VERSION 5.7 ;
  NOWIREEXTENSIONATPIN ON ;
  DIVIDERCHAR "/" ;
  BUSBITCHARS "[]" ;
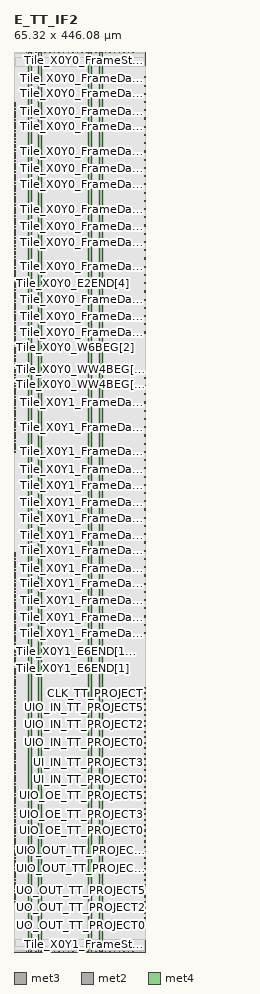
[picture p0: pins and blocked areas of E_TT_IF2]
MACRO E_TT_IF2
  CLASS BLOCK ;
  FOREIGN E_TT_IF2 ;
  ORIGIN 0.000 0.000 ;
  SIZE 65.320 BY 446.080 ;
  PIN CLK_TT_PROJECT
    DIRECTION OUTPUT ;
    USE SIGNAL ;
    ANTENNADIFFAREA 0.702900 ;
    PORT
      LAYER met3 ;
        RECT 64.720 127.880 65.320 128.480 ;
    END
  END CLK_TT_PROJECT
  PIN ENA_TT_PROJECT
    DIRECTION OUTPUT ;
    USE SIGNAL ;
    ANTENNADIFFAREA 0.702900 ;
    PORT
      LAYER met3 ;
        RECT 64.720 125.160 65.320 125.760 ;
    END
  END ENA_TT_PROJECT
  PIN RST_N_TT_PROJECT
    DIRECTION OUTPUT ;
    USE SIGNAL ;
    ANTENNADIFFAREA 0.702900 ;
    PORT
      LAYER met3 ;
        RECT 64.720 130.600 65.320 131.200 ;
    END
  END RST_N_TT_PROJECT
  PIN Tile_X0Y0_E1END[0]
    DIRECTION INPUT ;
    USE SIGNAL ;
    ANTENNAGATEAREA 0.570000 ;
    PORT
      LAYER met3 ;
        RECT 0.000 312.840 0.600 313.440 ;
    END
  END Tile_X0Y0_E1END[0]
  PIN Tile_X0Y0_E1END[1]
    DIRECTION INPUT ;
    USE SIGNAL ;
    ANTENNAGATEAREA 0.570000 ;
    PORT
      LAYER met3 ;
        RECT 0.000 314.200 0.600 314.800 ;
    END
  END Tile_X0Y0_E1END[1]
  PIN Tile_X0Y0_E1END[2]
    DIRECTION INPUT ;
    USE SIGNAL ;
    ANTENNAGATEAREA 1.439400 ;
    ANTENNADIFFAREA 0.869400 ;
    PORT
      LAYER met3 ;
        RECT 0.000 315.560 0.600 316.160 ;
    END
  END Tile_X0Y0_E1END[2]
  PIN Tile_X0Y0_E1END[3]
    DIRECTION INPUT ;
    USE SIGNAL ;
    ANTENNAGATEAREA 0.570000 ;
    PORT
      LAYER met3 ;
        RECT 0.000 316.920 0.600 317.520 ;
    END
  END Tile_X0Y0_E1END[3]
  PIN Tile_X0Y0_E2END[0]
    DIRECTION INPUT ;
    USE SIGNAL ;
    ANTENNAGATEAREA 1.308000 ;
    PORT
      LAYER met3 ;
        RECT 0.000 329.160 0.600 329.760 ;
    END
  END Tile_X0Y0_E2END[0]
  PIN Tile_X0Y0_E2END[1]
    DIRECTION INPUT ;
    USE SIGNAL ;
    ANTENNAGATEAREA 1.308000 ;
    PORT
      LAYER met3 ;
        RECT 0.000 330.520 0.600 331.120 ;
    END
  END Tile_X0Y0_E2END[1]
  PIN Tile_X0Y0_E2END[2]
    DIRECTION INPUT ;
    USE SIGNAL ;
    ANTENNAGATEAREA 1.308000 ;
    PORT
      LAYER met3 ;
        RECT 0.000 331.880 0.600 332.480 ;
    END
  END Tile_X0Y0_E2END[2]
  PIN Tile_X0Y0_E2END[3]
    DIRECTION INPUT ;
    USE SIGNAL ;
    ANTENNAGATEAREA 1.308000 ;
    PORT
      LAYER met3 ;
        RECT 0.000 333.240 0.600 333.840 ;
    END
  END Tile_X0Y0_E2END[3]
  PIN Tile_X0Y0_E2END[4]
    DIRECTION INPUT ;
    USE SIGNAL ;
    ANTENNAGATEAREA 1.396500 ;
    PORT
      LAYER met3 ;
        RECT 0.000 334.600 0.600 335.200 ;
    END
  END Tile_X0Y0_E2END[4]
  PIN Tile_X0Y0_E2END[5]
    DIRECTION INPUT ;
    USE SIGNAL ;
    ANTENNAGATEAREA 1.396500 ;
    PORT
      LAYER met3 ;
        RECT 0.000 335.960 0.600 336.560 ;
    END
  END Tile_X0Y0_E2END[5]
  PIN Tile_X0Y0_E2END[6]
    DIRECTION INPUT ;
    USE SIGNAL ;
    ANTENNAGATEAREA 0.901500 ;
    PORT
      LAYER met3 ;
        RECT 0.000 337.320 0.600 337.920 ;
    END
  END Tile_X0Y0_E2END[6]
  PIN Tile_X0Y0_E2END[7]
    DIRECTION INPUT ;
    USE SIGNAL ;
    ANTENNAGATEAREA 0.901500 ;
    PORT
      LAYER met3 ;
        RECT 0.000 338.680 0.600 339.280 ;
    END
  END Tile_X0Y0_E2END[7]
  PIN Tile_X0Y0_E2MID[0]
    DIRECTION INPUT ;
    USE SIGNAL ;
    ANTENNAGATEAREA 0.126000 ;
    PORT
      LAYER met3 ;
        RECT 0.000 318.280 0.600 318.880 ;
    END
  END Tile_X0Y0_E2MID[0]
  PIN Tile_X0Y0_E2MID[1]
    DIRECTION INPUT ;
    USE SIGNAL ;
    ANTENNAGATEAREA 0.560700 ;
    ANTENNADIFFAREA 0.434700 ;
    PORT
      LAYER met3 ;
        RECT 0.000 319.640 0.600 320.240 ;
    END
  END Tile_X0Y0_E2MID[1]
  PIN Tile_X0Y0_E2MID[2]
    DIRECTION INPUT ;
    USE SIGNAL ;
    ANTENNAGATEAREA 0.560700 ;
    ANTENNADIFFAREA 0.434700 ;
    PORT
      LAYER met3 ;
        RECT 0.000 321.000 0.600 321.600 ;
    END
  END Tile_X0Y0_E2MID[2]
  PIN Tile_X0Y0_E2MID[3]
    DIRECTION INPUT ;
    USE SIGNAL ;
    ANTENNAGATEAREA 0.560700 ;
    ANTENNADIFFAREA 0.434700 ;
    PORT
      LAYER met3 ;
        RECT 0.000 322.360 0.600 322.960 ;
    END
  END Tile_X0Y0_E2MID[3]
  PIN Tile_X0Y0_E2MID[4]
    DIRECTION INPUT ;
    USE SIGNAL ;
    ANTENNAGATEAREA 0.560700 ;
    ANTENNADIFFAREA 0.434700 ;
    PORT
      LAYER met3 ;
        RECT 0.000 323.720 0.600 324.320 ;
    END
  END Tile_X0Y0_E2MID[4]
  PIN Tile_X0Y0_E2MID[5]
    DIRECTION INPUT ;
    USE SIGNAL ;
    ANTENNAGATEAREA 0.560700 ;
    ANTENNADIFFAREA 0.434700 ;
    PORT
      LAYER met3 ;
        RECT 0.000 325.080 0.600 325.680 ;
    END
  END Tile_X0Y0_E2MID[5]
  PIN Tile_X0Y0_E2MID[6]
    DIRECTION INPUT ;
    USE SIGNAL ;
    ANTENNAGATEAREA 0.560700 ;
    ANTENNADIFFAREA 0.434700 ;
    PORT
      LAYER met3 ;
        RECT 0.000 326.440 0.600 327.040 ;
    END
  END Tile_X0Y0_E2MID[6]
  PIN Tile_X0Y0_E2MID[7]
    DIRECTION INPUT ;
    USE SIGNAL ;
    ANTENNAGATEAREA 0.560700 ;
    ANTENNADIFFAREA 0.434700 ;
    PORT
      LAYER met3 ;
        RECT 0.000 327.800 0.600 328.400 ;
    END
  END Tile_X0Y0_E2MID[7]
  PIN Tile_X0Y0_E6END[0]
    DIRECTION INPUT ;
    USE SIGNAL ;
    ANTENNAGATEAREA 0.663000 ;
    PORT
      LAYER met3 ;
        RECT 0.000 361.800 0.600 362.400 ;
    END
  END Tile_X0Y0_E6END[0]
  PIN Tile_X0Y0_E6END[10]
    DIRECTION INPUT ;
    USE SIGNAL ;
    ANTENNAGATEAREA 0.126000 ;
    PORT
      LAYER met3 ;
        RECT 0.000 375.400 0.600 376.000 ;
    END
  END Tile_X0Y0_E6END[10]
  PIN Tile_X0Y0_E6END[11]
    DIRECTION INPUT ;
    USE SIGNAL ;
    ANTENNAGATEAREA 0.411000 ;
    PORT
      LAYER met3 ;
        RECT 0.000 376.760 0.600 377.360 ;
    END
  END Tile_X0Y0_E6END[11]
  PIN Tile_X0Y0_E6END[1]
    DIRECTION INPUT ;
    USE SIGNAL ;
    ANTENNAGATEAREA 0.378000 ;
    PORT
      LAYER met3 ;
        RECT 0.000 363.160 0.600 363.760 ;
    END
  END Tile_X0Y0_E6END[1]
  PIN Tile_X0Y0_E6END[2]
    DIRECTION INPUT ;
    USE SIGNAL ;
    ANTENNAGATEAREA 0.378000 ;
    PORT
      LAYER met3 ;
        RECT 0.000 364.520 0.600 365.120 ;
    END
  END Tile_X0Y0_E6END[2]
  PIN Tile_X0Y0_E6END[3]
    DIRECTION INPUT ;
    USE SIGNAL ;
    ANTENNAGATEAREA 0.812700 ;
    ANTENNADIFFAREA 0.434700 ;
    PORT
      LAYER met3 ;
        RECT 0.000 365.880 0.600 366.480 ;
    END
  END Tile_X0Y0_E6END[3]
  PIN Tile_X0Y0_E6END[4]
    DIRECTION INPUT ;
    USE SIGNAL ;
    ANTENNAGATEAREA 0.411000 ;
    PORT
      LAYER met3 ;
        RECT 0.000 367.240 0.600 367.840 ;
    END
  END Tile_X0Y0_E6END[4]
  PIN Tile_X0Y0_E6END[5]
    DIRECTION INPUT ;
    USE SIGNAL ;
    ANTENNAGATEAREA 0.126000 ;
    PORT
      LAYER met3 ;
        RECT 0.000 368.600 0.600 369.200 ;
    END
  END Tile_X0Y0_E6END[5]
  PIN Tile_X0Y0_E6END[6]
    DIRECTION INPUT ;
    USE SIGNAL ;
    ANTENNAGATEAREA 1.121400 ;
    ANTENNADIFFAREA 0.869400 ;
    PORT
      LAYER met3 ;
        RECT 0.000 369.960 0.600 370.560 ;
    END
  END Tile_X0Y0_E6END[6]
  PIN Tile_X0Y0_E6END[7]
    DIRECTION INPUT ;
    USE SIGNAL ;
    ANTENNAGATEAREA 0.252000 ;
    PORT
      LAYER met3 ;
        RECT 0.000 371.320 0.600 371.920 ;
    END
  END Tile_X0Y0_E6END[7]
  PIN Tile_X0Y0_E6END[8]
    DIRECTION INPUT ;
    USE SIGNAL ;
    ANTENNAGATEAREA 0.537000 ;
    PORT
      LAYER met3 ;
        RECT 0.000 372.680 0.600 373.280 ;
    END
  END Tile_X0Y0_E6END[8]
  PIN Tile_X0Y0_E6END[9]
    DIRECTION INPUT ;
    USE SIGNAL ;
    ANTENNAGATEAREA 0.252000 ;
    PORT
      LAYER met3 ;
        RECT 0.000 374.040 0.600 374.640 ;
    END
  END Tile_X0Y0_E6END[9]
  PIN Tile_X0Y0_EE4END[0]
    DIRECTION INPUT ;
    USE SIGNAL ;
    ANTENNAGATEAREA 0.663000 ;
    PORT
      LAYER met3 ;
        RECT 0.000 340.040 0.600 340.640 ;
    END
  END Tile_X0Y0_EE4END[0]
  PIN Tile_X0Y0_EE4END[10]
    DIRECTION INPUT ;
    USE SIGNAL ;
    ANTENNAGATEAREA 0.906000 ;
    PORT
      LAYER met3 ;
        RECT 0.000 353.640 0.600 354.240 ;
    END
  END Tile_X0Y0_EE4END[10]
  PIN Tile_X0Y0_EE4END[11]
    DIRECTION INPUT ;
    USE SIGNAL ;
    ANTENNAGATEAREA 1.340700 ;
    ANTENNADIFFAREA 0.434700 ;
    PORT
      LAYER met3 ;
        RECT 0.000 355.000 0.600 355.600 ;
    END
  END Tile_X0Y0_EE4END[11]
  PIN Tile_X0Y0_EE4END[12]
    DIRECTION INPUT ;
    USE SIGNAL ;
    ANTENNAGATEAREA 0.906000 ;
    PORT
      LAYER met3 ;
        RECT 0.000 356.360 0.600 356.960 ;
    END
  END Tile_X0Y0_EE4END[12]
  PIN Tile_X0Y0_EE4END[13]
    DIRECTION INPUT ;
    USE SIGNAL ;
    ANTENNAGATEAREA 0.906000 ;
    PORT
      LAYER met3 ;
        RECT 0.000 357.720 0.600 358.320 ;
    END
  END Tile_X0Y0_EE4END[13]
  PIN Tile_X0Y0_EE4END[14]
    DIRECTION INPUT ;
    USE SIGNAL ;
    ANTENNAGATEAREA 0.906000 ;
    PORT
      LAYER met3 ;
        RECT 0.000 359.080 0.600 359.680 ;
    END
  END Tile_X0Y0_EE4END[14]
  PIN Tile_X0Y0_EE4END[15]
    DIRECTION INPUT ;
    USE SIGNAL ;
    ANTENNAGATEAREA 0.906000 ;
    PORT
      LAYER met3 ;
        RECT 0.000 360.440 0.600 361.040 ;
    END
  END Tile_X0Y0_EE4END[15]
  PIN Tile_X0Y0_EE4END[1]
    DIRECTION INPUT ;
    USE SIGNAL ;
    ANTENNAGATEAREA 0.663000 ;
    PORT
      LAYER met3 ;
        RECT 0.000 341.400 0.600 342.000 ;
    END
  END Tile_X0Y0_EE4END[1]
  PIN Tile_X0Y0_EE4END[2]
    DIRECTION INPUT ;
    USE SIGNAL ;
    ANTENNAGATEAREA 0.663000 ;
    PORT
      LAYER met3 ;
        RECT 0.000 342.760 0.600 343.360 ;
    END
  END Tile_X0Y0_EE4END[2]
  PIN Tile_X0Y0_EE4END[3]
    DIRECTION INPUT ;
    USE SIGNAL ;
    ANTENNAGATEAREA 0.663000 ;
    PORT
      LAYER met3 ;
        RECT 0.000 344.120 0.600 344.720 ;
    END
  END Tile_X0Y0_EE4END[3]
  PIN Tile_X0Y0_EE4END[4]
    DIRECTION INPUT ;
    USE SIGNAL ;
    ANTENNAGATEAREA 0.971700 ;
    ANTENNADIFFAREA 0.434700 ;
    PORT
      LAYER met3 ;
        RECT 0.000 345.480 0.600 346.080 ;
    END
  END Tile_X0Y0_EE4END[4]
  PIN Tile_X0Y0_EE4END[5]
    DIRECTION INPUT ;
    USE SIGNAL ;
    ANTENNAGATEAREA 0.537000 ;
    PORT
      LAYER met3 ;
        RECT 0.000 346.840 0.600 347.440 ;
    END
  END Tile_X0Y0_EE4END[5]
  PIN Tile_X0Y0_EE4END[6]
    DIRECTION INPUT ;
    USE SIGNAL ;
    ANTENNAGATEAREA 0.537000 ;
    PORT
      LAYER met3 ;
        RECT 0.000 348.200 0.600 348.800 ;
    END
  END Tile_X0Y0_EE4END[6]
  PIN Tile_X0Y0_EE4END[7]
    DIRECTION INPUT ;
    USE SIGNAL ;
    ANTENNAGATEAREA 0.537000 ;
    PORT
      LAYER met3 ;
        RECT 0.000 349.560 0.600 350.160 ;
    END
  END Tile_X0Y0_EE4END[7]
  PIN Tile_X0Y0_EE4END[8]
    DIRECTION INPUT ;
    USE SIGNAL ;
    ANTENNAGATEAREA 0.906000 ;
    PORT
      LAYER met3 ;
        RECT 0.000 350.920 0.600 351.520 ;
    END
  END Tile_X0Y0_EE4END[8]
  PIN Tile_X0Y0_EE4END[9]
    DIRECTION INPUT ;
    USE SIGNAL ;
    ANTENNAGATEAREA 0.906000 ;
    PORT
      LAYER met3 ;
        RECT 0.000 352.280 0.600 352.880 ;
    END
  END Tile_X0Y0_EE4END[9]
  PIN Tile_X0Y0_FrameData[0]
    DIRECTION INPUT ;
    USE SIGNAL ;
    ANTENNAGATEAREA 0.636000 ;
    PORT
      LAYER met3 ;
        RECT 0.000 378.120 0.600 378.720 ;
    END
  END Tile_X0Y0_FrameData[0]
  PIN Tile_X0Y0_FrameData[10]
    DIRECTION INPUT ;
    USE SIGNAL ;
    ANTENNAGATEAREA 0.795000 ;
    PORT
      LAYER met3 ;
        RECT 0.000 391.720 0.600 392.320 ;
    END
  END Tile_X0Y0_FrameData[10]
  PIN Tile_X0Y0_FrameData[11]
    DIRECTION INPUT ;
    USE SIGNAL ;
    ANTENNAGATEAREA 0.795000 ;
    PORT
      LAYER met3 ;
        RECT 0.000 393.080 0.600 393.680 ;
    END
  END Tile_X0Y0_FrameData[11]
  PIN Tile_X0Y0_FrameData[12]
    DIRECTION INPUT ;
    USE SIGNAL ;
    ANTENNAGATEAREA 0.795000 ;
    PORT
      LAYER met3 ;
        RECT 0.000 394.440 0.600 395.040 ;
    END
  END Tile_X0Y0_FrameData[12]
  PIN Tile_X0Y0_FrameData[13]
    DIRECTION INPUT ;
    USE SIGNAL ;
    ANTENNAGATEAREA 0.795000 ;
    PORT
      LAYER met3 ;
        RECT 0.000 395.800 0.600 396.400 ;
    END
  END Tile_X0Y0_FrameData[13]
  PIN Tile_X0Y0_FrameData[14]
    DIRECTION INPUT ;
    USE SIGNAL ;
    ANTENNAGATEAREA 0.795000 ;
    PORT
      LAYER met3 ;
        RECT 0.000 397.160 0.600 397.760 ;
    END
  END Tile_X0Y0_FrameData[14]
  PIN Tile_X0Y0_FrameData[15]
    DIRECTION INPUT ;
    USE SIGNAL ;
    ANTENNAGATEAREA 0.795000 ;
    PORT
      LAYER met3 ;
        RECT 0.000 398.520 0.600 399.120 ;
    END
  END Tile_X0Y0_FrameData[15]
  PIN Tile_X0Y0_FrameData[16]
    DIRECTION INPUT ;
    USE SIGNAL ;
    ANTENNAGATEAREA 0.795000 ;
    PORT
      LAYER met3 ;
        RECT 0.000 399.880 0.600 400.480 ;
    END
  END Tile_X0Y0_FrameData[16]
  PIN Tile_X0Y0_FrameData[17]
    DIRECTION INPUT ;
    USE SIGNAL ;
    ANTENNAGATEAREA 0.795000 ;
    PORT
      LAYER met3 ;
        RECT 0.000 401.240 0.600 401.840 ;
    END
  END Tile_X0Y0_FrameData[17]
  PIN Tile_X0Y0_FrameData[18]
    DIRECTION INPUT ;
    USE SIGNAL ;
    ANTENNAGATEAREA 0.795000 ;
    PORT
      LAYER met3 ;
        RECT 0.000 402.600 0.600 403.200 ;
    END
  END Tile_X0Y0_FrameData[18]
  PIN Tile_X0Y0_FrameData[19]
    DIRECTION INPUT ;
    USE SIGNAL ;
    ANTENNAGATEAREA 0.795000 ;
    PORT
      LAYER met3 ;
        RECT 0.000 403.960 0.600 404.560 ;
    END
  END Tile_X0Y0_FrameData[19]
  PIN Tile_X0Y0_FrameData[1]
    DIRECTION INPUT ;
    USE SIGNAL ;
    ANTENNAGATEAREA 0.636000 ;
    PORT
      LAYER met3 ;
        RECT 0.000 379.480 0.600 380.080 ;
    END
  END Tile_X0Y0_FrameData[1]
  PIN Tile_X0Y0_FrameData[20]
    DIRECTION INPUT ;
    USE SIGNAL ;
    ANTENNAGATEAREA 0.795000 ;
    PORT
      LAYER met3 ;
        RECT 0.000 405.320 0.600 405.920 ;
    END
  END Tile_X0Y0_FrameData[20]
  PIN Tile_X0Y0_FrameData[21]
    DIRECTION INPUT ;
    USE SIGNAL ;
    ANTENNAGATEAREA 0.795000 ;
    PORT
      LAYER met3 ;
        RECT 0.000 406.680 0.600 407.280 ;
    END
  END Tile_X0Y0_FrameData[21]
  PIN Tile_X0Y0_FrameData[22]
    DIRECTION INPUT ;
    USE SIGNAL ;
    ANTENNAGATEAREA 0.795000 ;
    PORT
      LAYER met3 ;
        RECT 0.000 408.040 0.600 408.640 ;
    END
  END Tile_X0Y0_FrameData[22]
  PIN Tile_X0Y0_FrameData[23]
    DIRECTION INPUT ;
    USE SIGNAL ;
    ANTENNAGATEAREA 0.795000 ;
    PORT
      LAYER met3 ;
        RECT 0.000 409.400 0.600 410.000 ;
    END
  END Tile_X0Y0_FrameData[23]
  PIN Tile_X0Y0_FrameData[24]
    DIRECTION INPUT ;
    USE SIGNAL ;
    ANTENNAGATEAREA 0.795000 ;
    PORT
      LAYER met3 ;
        RECT 0.000 410.760 0.600 411.360 ;
    END
  END Tile_X0Y0_FrameData[24]
  PIN Tile_X0Y0_FrameData[25]
    DIRECTION INPUT ;
    USE SIGNAL ;
    ANTENNAGATEAREA 0.795000 ;
    PORT
      LAYER met3 ;
        RECT 0.000 412.120 0.600 412.720 ;
    END
  END Tile_X0Y0_FrameData[25]
  PIN Tile_X0Y0_FrameData[26]
    DIRECTION INPUT ;
    USE SIGNAL ;
    ANTENNAGATEAREA 0.795000 ;
    PORT
      LAYER met3 ;
        RECT 0.000 413.480 0.600 414.080 ;
    END
  END Tile_X0Y0_FrameData[26]
  PIN Tile_X0Y0_FrameData[27]
    DIRECTION INPUT ;
    USE SIGNAL ;
    ANTENNAGATEAREA 0.795000 ;
    PORT
      LAYER met3 ;
        RECT 0.000 414.840 0.600 415.440 ;
    END
  END Tile_X0Y0_FrameData[27]
  PIN Tile_X0Y0_FrameData[28]
    DIRECTION INPUT ;
    USE SIGNAL ;
    ANTENNAGATEAREA 0.795000 ;
    PORT
      LAYER met3 ;
        RECT 0.000 416.200 0.600 416.800 ;
    END
  END Tile_X0Y0_FrameData[28]
  PIN Tile_X0Y0_FrameData[29]
    DIRECTION INPUT ;
    USE SIGNAL ;
    ANTENNAGATEAREA 0.795000 ;
    PORT
      LAYER met3 ;
        RECT 0.000 417.560 0.600 418.160 ;
    END
  END Tile_X0Y0_FrameData[29]
  PIN Tile_X0Y0_FrameData[2]
    DIRECTION INPUT ;
    USE SIGNAL ;
    ANTENNAGATEAREA 0.636000 ;
    PORT
      LAYER met3 ;
        RECT 0.000 380.840 0.600 381.440 ;
    END
  END Tile_X0Y0_FrameData[2]
  PIN Tile_X0Y0_FrameData[30]
    DIRECTION INPUT ;
    USE SIGNAL ;
    ANTENNAGATEAREA 0.795000 ;
    PORT
      LAYER met3 ;
        RECT 0.000 418.920 0.600 419.520 ;
    END
  END Tile_X0Y0_FrameData[30]
  PIN Tile_X0Y0_FrameData[31]
    DIRECTION INPUT ;
    USE SIGNAL ;
    ANTENNAGATEAREA 0.795000 ;
    PORT
      LAYER met3 ;
        RECT 0.000 420.280 0.600 420.880 ;
    END
  END Tile_X0Y0_FrameData[31]
  PIN Tile_X0Y0_FrameData[3]
    DIRECTION INPUT ;
    USE SIGNAL ;
    ANTENNAGATEAREA 0.636000 ;
    PORT
      LAYER met3 ;
        RECT 0.000 382.200 0.600 382.800 ;
    END
  END Tile_X0Y0_FrameData[3]
  PIN Tile_X0Y0_FrameData[4]
    DIRECTION INPUT ;
    USE SIGNAL ;
    ANTENNAGATEAREA 0.795000 ;
    PORT
      LAYER met3 ;
        RECT 0.000 383.560 0.600 384.160 ;
    END
  END Tile_X0Y0_FrameData[4]
  PIN Tile_X0Y0_FrameData[5]
    DIRECTION INPUT ;
    USE SIGNAL ;
    ANTENNAGATEAREA 0.795000 ;
    PORT
      LAYER met3 ;
        RECT 0.000 384.920 0.600 385.520 ;
    END
  END Tile_X0Y0_FrameData[5]
  PIN Tile_X0Y0_FrameData[6]
    DIRECTION INPUT ;
    USE SIGNAL ;
    ANTENNAGATEAREA 1.229700 ;
    ANTENNADIFFAREA 0.434700 ;
    PORT
      LAYER met3 ;
        RECT 0.000 386.280 0.600 386.880 ;
    END
  END Tile_X0Y0_FrameData[6]
  PIN Tile_X0Y0_FrameData[7]
    DIRECTION INPUT ;
    USE SIGNAL ;
    ANTENNAGATEAREA 0.795000 ;
    PORT
      LAYER met3 ;
        RECT 0.000 387.640 0.600 388.240 ;
    END
  END Tile_X0Y0_FrameData[7]
  PIN Tile_X0Y0_FrameData[8]
    DIRECTION INPUT ;
    USE SIGNAL ;
    ANTENNAGATEAREA 0.795000 ;
    PORT
      LAYER met3 ;
        RECT 0.000 389.000 0.600 389.600 ;
    END
  END Tile_X0Y0_FrameData[8]
  PIN Tile_X0Y0_FrameData[9]
    DIRECTION INPUT ;
    USE SIGNAL ;
    ANTENNAGATEAREA 0.795000 ;
    PORT
      LAYER met3 ;
        RECT 0.000 390.360 0.600 390.960 ;
    END
  END Tile_X0Y0_FrameData[9]
  PIN Tile_X0Y0_FrameData_O[0]
    DIRECTION OUTPUT ;
    USE SIGNAL ;
    ANTENNADIFFAREA 0.702900 ;
    PORT
      LAYER met3 ;
        RECT 64.720 306.720 65.320 307.320 ;
    END
  END Tile_X0Y0_FrameData_O[0]
  PIN Tile_X0Y0_FrameData_O[10]
    DIRECTION OUTPUT ;
    USE SIGNAL ;
    ANTENNADIFFAREA 0.702900 ;
    PORT
      LAYER met3 ;
        RECT 64.720 347.520 65.320 348.120 ;
    END
  END Tile_X0Y0_FrameData_O[10]
  PIN Tile_X0Y0_FrameData_O[11]
    DIRECTION OUTPUT ;
    USE SIGNAL ;
    ANTENNADIFFAREA 0.702900 ;
    PORT
      LAYER met3 ;
        RECT 64.720 351.600 65.320 352.200 ;
    END
  END Tile_X0Y0_FrameData_O[11]
  PIN Tile_X0Y0_FrameData_O[12]
    DIRECTION OUTPUT ;
    USE SIGNAL ;
    ANTENNADIFFAREA 0.702900 ;
    PORT
      LAYER met3 ;
        RECT 64.720 355.680 65.320 356.280 ;
    END
  END Tile_X0Y0_FrameData_O[12]
  PIN Tile_X0Y0_FrameData_O[13]
    DIRECTION OUTPUT ;
    USE SIGNAL ;
    ANTENNADIFFAREA 0.702900 ;
    PORT
      LAYER met3 ;
        RECT 64.720 359.760 65.320 360.360 ;
    END
  END Tile_X0Y0_FrameData_O[13]
  PIN Tile_X0Y0_FrameData_O[14]
    DIRECTION OUTPUT ;
    USE SIGNAL ;
    ANTENNADIFFAREA 0.702900 ;
    PORT
      LAYER met3 ;
        RECT 64.720 363.840 65.320 364.440 ;
    END
  END Tile_X0Y0_FrameData_O[14]
  PIN Tile_X0Y0_FrameData_O[15]
    DIRECTION OUTPUT ;
    USE SIGNAL ;
    ANTENNADIFFAREA 0.702900 ;
    PORT
      LAYER met3 ;
        RECT 64.720 367.920 65.320 368.520 ;
    END
  END Tile_X0Y0_FrameData_O[15]
  PIN Tile_X0Y0_FrameData_O[16]
    DIRECTION OUTPUT ;
    USE SIGNAL ;
    ANTENNADIFFAREA 0.702900 ;
    PORT
      LAYER met3 ;
        RECT 64.720 372.000 65.320 372.600 ;
    END
  END Tile_X0Y0_FrameData_O[16]
  PIN Tile_X0Y0_FrameData_O[17]
    DIRECTION OUTPUT ;
    USE SIGNAL ;
    ANTENNADIFFAREA 0.702900 ;
    PORT
      LAYER met3 ;
        RECT 64.720 376.080 65.320 376.680 ;
    END
  END Tile_X0Y0_FrameData_O[17]
  PIN Tile_X0Y0_FrameData_O[18]
    DIRECTION OUTPUT ;
    USE SIGNAL ;
    ANTENNADIFFAREA 0.702900 ;
    PORT
      LAYER met3 ;
        RECT 64.720 380.160 65.320 380.760 ;
    END
  END Tile_X0Y0_FrameData_O[18]
  PIN Tile_X0Y0_FrameData_O[19]
    DIRECTION OUTPUT ;
    USE SIGNAL ;
    ANTENNADIFFAREA 0.702900 ;
    PORT
      LAYER met3 ;
        RECT 64.720 384.240 65.320 384.840 ;
    END
  END Tile_X0Y0_FrameData_O[19]
  PIN Tile_X0Y0_FrameData_O[1]
    DIRECTION OUTPUT ;
    USE SIGNAL ;
    ANTENNADIFFAREA 0.702900 ;
    PORT
      LAYER met3 ;
        RECT 64.720 310.800 65.320 311.400 ;
    END
  END Tile_X0Y0_FrameData_O[1]
  PIN Tile_X0Y0_FrameData_O[20]
    DIRECTION OUTPUT ;
    USE SIGNAL ;
    ANTENNADIFFAREA 0.702900 ;
    PORT
      LAYER met3 ;
        RECT 64.720 388.320 65.320 388.920 ;
    END
  END Tile_X0Y0_FrameData_O[20]
  PIN Tile_X0Y0_FrameData_O[21]
    DIRECTION OUTPUT ;
    USE SIGNAL ;
    ANTENNADIFFAREA 0.702900 ;
    PORT
      LAYER met3 ;
        RECT 64.720 392.400 65.320 393.000 ;
    END
  END Tile_X0Y0_FrameData_O[21]
  PIN Tile_X0Y0_FrameData_O[22]
    DIRECTION OUTPUT ;
    USE SIGNAL ;
    ANTENNADIFFAREA 0.702900 ;
    PORT
      LAYER met3 ;
        RECT 64.720 396.480 65.320 397.080 ;
    END
  END Tile_X0Y0_FrameData_O[22]
  PIN Tile_X0Y0_FrameData_O[23]
    DIRECTION OUTPUT ;
    USE SIGNAL ;
    ANTENNADIFFAREA 0.702900 ;
    PORT
      LAYER met3 ;
        RECT 64.720 400.560 65.320 401.160 ;
    END
  END Tile_X0Y0_FrameData_O[23]
  PIN Tile_X0Y0_FrameData_O[24]
    DIRECTION OUTPUT ;
    USE SIGNAL ;
    ANTENNADIFFAREA 0.702900 ;
    PORT
      LAYER met3 ;
        RECT 64.720 404.640 65.320 405.240 ;
    END
  END Tile_X0Y0_FrameData_O[24]
  PIN Tile_X0Y0_FrameData_O[25]
    DIRECTION OUTPUT ;
    USE SIGNAL ;
    ANTENNADIFFAREA 0.702900 ;
    PORT
      LAYER met3 ;
        RECT 64.720 408.720 65.320 409.320 ;
    END
  END Tile_X0Y0_FrameData_O[25]
  PIN Tile_X0Y0_FrameData_O[26]
    DIRECTION OUTPUT ;
    USE SIGNAL ;
    ANTENNADIFFAREA 0.702900 ;
    PORT
      LAYER met3 ;
        RECT 64.720 412.800 65.320 413.400 ;
    END
  END Tile_X0Y0_FrameData_O[26]
  PIN Tile_X0Y0_FrameData_O[27]
    DIRECTION OUTPUT ;
    USE SIGNAL ;
    ANTENNADIFFAREA 0.702900 ;
    PORT
      LAYER met3 ;
        RECT 64.720 416.880 65.320 417.480 ;
    END
  END Tile_X0Y0_FrameData_O[27]
  PIN Tile_X0Y0_FrameData_O[28]
    DIRECTION OUTPUT ;
    USE SIGNAL ;
    ANTENNADIFFAREA 0.702900 ;
    PORT
      LAYER met3 ;
        RECT 64.720 420.960 65.320 421.560 ;
    END
  END Tile_X0Y0_FrameData_O[28]
  PIN Tile_X0Y0_FrameData_O[29]
    DIRECTION OUTPUT ;
    USE SIGNAL ;
    ANTENNADIFFAREA 0.702900 ;
    PORT
      LAYER met3 ;
        RECT 64.720 425.040 65.320 425.640 ;
    END
  END Tile_X0Y0_FrameData_O[29]
  PIN Tile_X0Y0_FrameData_O[2]
    DIRECTION OUTPUT ;
    USE SIGNAL ;
    ANTENNADIFFAREA 0.702900 ;
    PORT
      LAYER met3 ;
        RECT 64.720 314.880 65.320 315.480 ;
    END
  END Tile_X0Y0_FrameData_O[2]
  PIN Tile_X0Y0_FrameData_O[30]
    DIRECTION OUTPUT ;
    USE SIGNAL ;
    ANTENNADIFFAREA 0.702900 ;
    PORT
      LAYER met3 ;
        RECT 64.720 429.120 65.320 429.720 ;
    END
  END Tile_X0Y0_FrameData_O[30]
  PIN Tile_X0Y0_FrameData_O[31]
    DIRECTION OUTPUT ;
    USE SIGNAL ;
    ANTENNADIFFAREA 0.702900 ;
    PORT
      LAYER met3 ;
        RECT 64.720 433.200 65.320 433.800 ;
    END
  END Tile_X0Y0_FrameData_O[31]
  PIN Tile_X0Y0_FrameData_O[3]
    DIRECTION OUTPUT ;
    USE SIGNAL ;
    ANTENNADIFFAREA 0.702900 ;
    PORT
      LAYER met3 ;
        RECT 64.720 318.960 65.320 319.560 ;
    END
  END Tile_X0Y0_FrameData_O[3]
  PIN Tile_X0Y0_FrameData_O[4]
    DIRECTION OUTPUT ;
    USE SIGNAL ;
    ANTENNADIFFAREA 0.702900 ;
    PORT
      LAYER met3 ;
        RECT 64.720 323.040 65.320 323.640 ;
    END
  END Tile_X0Y0_FrameData_O[4]
  PIN Tile_X0Y0_FrameData_O[5]
    DIRECTION OUTPUT ;
    USE SIGNAL ;
    ANTENNADIFFAREA 0.702900 ;
    PORT
      LAYER met3 ;
        RECT 64.720 327.120 65.320 327.720 ;
    END
  END Tile_X0Y0_FrameData_O[5]
  PIN Tile_X0Y0_FrameData_O[6]
    DIRECTION OUTPUT ;
    USE SIGNAL ;
    ANTENNADIFFAREA 0.702900 ;
    PORT
      LAYER met3 ;
        RECT 64.720 331.200 65.320 331.800 ;
    END
  END Tile_X0Y0_FrameData_O[6]
  PIN Tile_X0Y0_FrameData_O[7]
    DIRECTION OUTPUT ;
    USE SIGNAL ;
    ANTENNADIFFAREA 0.702900 ;
    PORT
      LAYER met3 ;
        RECT 64.720 335.280 65.320 335.880 ;
    END
  END Tile_X0Y0_FrameData_O[7]
  PIN Tile_X0Y0_FrameData_O[8]
    DIRECTION OUTPUT ;
    USE SIGNAL ;
    ANTENNADIFFAREA 0.702900 ;
    PORT
      LAYER met3 ;
        RECT 64.720 339.360 65.320 339.960 ;
    END
  END Tile_X0Y0_FrameData_O[8]
  PIN Tile_X0Y0_FrameData_O[9]
    DIRECTION OUTPUT ;
    USE SIGNAL ;
    ANTENNADIFFAREA 0.702900 ;
    PORT
      LAYER met3 ;
        RECT 64.720 343.440 65.320 344.040 ;
    END
  END Tile_X0Y0_FrameData_O[9]
  PIN Tile_X0Y0_FrameStrobe_O[0]
    DIRECTION OUTPUT ;
    USE SIGNAL ;
    ANTENNADIFFAREA 0.702900 ;
    PORT
      LAYER met2 ;
        RECT 15.270 445.800 15.550 446.080 ;
    END
  END Tile_X0Y0_FrameStrobe_O[0]
  PIN Tile_X0Y0_FrameStrobe_O[10]
    DIRECTION OUTPUT ;
    USE SIGNAL ;
    ANTENNADIFFAREA 0.702900 ;
    PORT
      LAYER met2 ;
        RECT 38.270 445.800 38.550 446.080 ;
    END
  END Tile_X0Y0_FrameStrobe_O[10]
  PIN Tile_X0Y0_FrameStrobe_O[11]
    DIRECTION OUTPUT ;
    USE SIGNAL ;
    ANTENNADIFFAREA 0.702900 ;
    PORT
      LAYER met2 ;
        RECT 40.570 445.800 40.850 446.080 ;
    END
  END Tile_X0Y0_FrameStrobe_O[11]
  PIN Tile_X0Y0_FrameStrobe_O[12]
    DIRECTION OUTPUT ;
    USE SIGNAL ;
    ANTENNADIFFAREA 0.702900 ;
    PORT
      LAYER met2 ;
        RECT 42.870 445.800 43.150 446.080 ;
    END
  END Tile_X0Y0_FrameStrobe_O[12]
  PIN Tile_X0Y0_FrameStrobe_O[13]
    DIRECTION OUTPUT ;
    USE SIGNAL ;
    ANTENNADIFFAREA 0.702900 ;
    PORT
      LAYER met2 ;
        RECT 45.170 445.800 45.450 446.080 ;
    END
  END Tile_X0Y0_FrameStrobe_O[13]
  PIN Tile_X0Y0_FrameStrobe_O[14]
    DIRECTION OUTPUT ;
    USE SIGNAL ;
    ANTENNADIFFAREA 0.702900 ;
    PORT
      LAYER met2 ;
        RECT 47.470 445.800 47.750 446.080 ;
    END
  END Tile_X0Y0_FrameStrobe_O[14]
  PIN Tile_X0Y0_FrameStrobe_O[15]
    DIRECTION OUTPUT ;
    USE SIGNAL ;
    ANTENNADIFFAREA 0.702900 ;
    PORT
      LAYER met2 ;
        RECT 49.770 445.800 50.050 446.080 ;
    END
  END Tile_X0Y0_FrameStrobe_O[15]
  PIN Tile_X0Y0_FrameStrobe_O[16]
    DIRECTION OUTPUT ;
    USE SIGNAL ;
    ANTENNADIFFAREA 0.702900 ;
    PORT
      LAYER met2 ;
        RECT 52.070 445.800 52.350 446.080 ;
    END
  END Tile_X0Y0_FrameStrobe_O[16]
  PIN Tile_X0Y0_FrameStrobe_O[17]
    DIRECTION OUTPUT ;
    USE SIGNAL ;
    ANTENNADIFFAREA 0.702900 ;
    PORT
      LAYER met2 ;
        RECT 54.370 445.800 54.650 446.080 ;
    END
  END Tile_X0Y0_FrameStrobe_O[17]
  PIN Tile_X0Y0_FrameStrobe_O[18]
    DIRECTION OUTPUT ;
    USE SIGNAL ;
    ANTENNADIFFAREA 0.702900 ;
    PORT
      LAYER met2 ;
        RECT 56.670 445.800 56.950 446.080 ;
    END
  END Tile_X0Y0_FrameStrobe_O[18]
  PIN Tile_X0Y0_FrameStrobe_O[19]
    DIRECTION OUTPUT ;
    USE SIGNAL ;
    ANTENNADIFFAREA 0.702900 ;
    PORT
      LAYER met2 ;
        RECT 58.970 445.800 59.250 446.080 ;
    END
  END Tile_X0Y0_FrameStrobe_O[19]
  PIN Tile_X0Y0_FrameStrobe_O[1]
    DIRECTION OUTPUT ;
    USE SIGNAL ;
    ANTENNADIFFAREA 0.702900 ;
    PORT
      LAYER met2 ;
        RECT 17.570 445.800 17.850 446.080 ;
    END
  END Tile_X0Y0_FrameStrobe_O[1]
  PIN Tile_X0Y0_FrameStrobe_O[2]
    DIRECTION OUTPUT ;
    USE SIGNAL ;
    ANTENNADIFFAREA 0.702900 ;
    PORT
      LAYER met2 ;
        RECT 19.870 445.800 20.150 446.080 ;
    END
  END Tile_X0Y0_FrameStrobe_O[2]
  PIN Tile_X0Y0_FrameStrobe_O[3]
    DIRECTION OUTPUT ;
    USE SIGNAL ;
    ANTENNADIFFAREA 0.702900 ;
    PORT
      LAYER met2 ;
        RECT 22.170 445.800 22.450 446.080 ;
    END
  END Tile_X0Y0_FrameStrobe_O[3]
  PIN Tile_X0Y0_FrameStrobe_O[4]
    DIRECTION OUTPUT ;
    USE SIGNAL ;
    ANTENNADIFFAREA 0.702900 ;
    PORT
      LAYER met2 ;
        RECT 24.470 445.800 24.750 446.080 ;
    END
  END Tile_X0Y0_FrameStrobe_O[4]
  PIN Tile_X0Y0_FrameStrobe_O[5]
    DIRECTION OUTPUT ;
    USE SIGNAL ;
    ANTENNADIFFAREA 0.702900 ;
    PORT
      LAYER met2 ;
        RECT 26.770 445.800 27.050 446.080 ;
    END
  END Tile_X0Y0_FrameStrobe_O[5]
  PIN Tile_X0Y0_FrameStrobe_O[6]
    DIRECTION OUTPUT ;
    USE SIGNAL ;
    ANTENNADIFFAREA 0.702900 ;
    PORT
      LAYER met2 ;
        RECT 29.070 445.800 29.350 446.080 ;
    END
  END Tile_X0Y0_FrameStrobe_O[6]
  PIN Tile_X0Y0_FrameStrobe_O[7]
    DIRECTION OUTPUT ;
    USE SIGNAL ;
    ANTENNADIFFAREA 0.702900 ;
    PORT
      LAYER met2 ;
        RECT 31.370 445.800 31.650 446.080 ;
    END
  END Tile_X0Y0_FrameStrobe_O[7]
  PIN Tile_X0Y0_FrameStrobe_O[8]
    DIRECTION OUTPUT ;
    USE SIGNAL ;
    ANTENNADIFFAREA 0.702900 ;
    PORT
      LAYER met2 ;
        RECT 33.670 445.800 33.950 446.080 ;
    END
  END Tile_X0Y0_FrameStrobe_O[8]
  PIN Tile_X0Y0_FrameStrobe_O[9]
    DIRECTION OUTPUT ;
    USE SIGNAL ;
    ANTENNADIFFAREA 0.702900 ;
    PORT
      LAYER met2 ;
        RECT 35.970 445.800 36.250 446.080 ;
    END
  END Tile_X0Y0_FrameStrobe_O[9]
  PIN Tile_X0Y0_N_GBUF_BEG[0]
    DIRECTION OUTPUT ;
    USE SIGNAL ;
    ANTENNADIFFAREA 0.702900 ;
    PORT
      LAYER met2 ;
        RECT 6.070 445.800 6.350 446.080 ;
    END
  END Tile_X0Y0_N_GBUF_BEG[0]
  PIN Tile_X0Y0_N_GBUF_BEG[1]
    DIRECTION OUTPUT ;
    USE SIGNAL ;
    ANTENNADIFFAREA 0.702900 ;
    PORT
      LAYER met2 ;
        RECT 8.370 445.800 8.650 446.080 ;
    END
  END Tile_X0Y0_N_GBUF_BEG[1]
  PIN Tile_X0Y0_N_GBUF_BEG[2]
    DIRECTION OUTPUT ;
    USE SIGNAL ;
    ANTENNADIFFAREA 0.702900 ;
    PORT
      LAYER met2 ;
        RECT 10.670 445.800 10.950 446.080 ;
    END
  END Tile_X0Y0_N_GBUF_BEG[2]
  PIN Tile_X0Y0_N_GBUF_BEG[3]
    DIRECTION OUTPUT ;
    USE SIGNAL ;
    ANTENNADIFFAREA 0.702900 ;
    PORT
      LAYER met2 ;
        RECT 12.970 445.800 13.250 446.080 ;
    END
  END Tile_X0Y0_N_GBUF_BEG[3]
  PIN Tile_X0Y0_W1BEG[0]
    DIRECTION OUTPUT ;
    USE SIGNAL ;
    ANTENNADIFFAREA 0.702900 ;
    PORT
      LAYER met3 ;
        RECT 0.000 247.560 0.600 248.160 ;
    END
  END Tile_X0Y0_W1BEG[0]
  PIN Tile_X0Y0_W1BEG[1]
    DIRECTION OUTPUT ;
    USE SIGNAL ;
    ANTENNADIFFAREA 0.702900 ;
    PORT
      LAYER met3 ;
        RECT 0.000 248.920 0.600 249.520 ;
    END
  END Tile_X0Y0_W1BEG[1]
  PIN Tile_X0Y0_W1BEG[2]
    DIRECTION OUTPUT ;
    USE SIGNAL ;
    ANTENNADIFFAREA 0.702900 ;
    PORT
      LAYER met3 ;
        RECT 0.000 250.280 0.600 250.880 ;
    END
  END Tile_X0Y0_W1BEG[2]
  PIN Tile_X0Y0_W1BEG[3]
    DIRECTION OUTPUT ;
    USE SIGNAL ;
    ANTENNADIFFAREA 0.702900 ;
    PORT
      LAYER met3 ;
        RECT 0.000 251.640 0.600 252.240 ;
    END
  END Tile_X0Y0_W1BEG[3]
  PIN Tile_X0Y0_W2BEG[0]
    DIRECTION OUTPUT ;
    USE SIGNAL ;
    ANTENNADIFFAREA 0.702900 ;
    PORT
      LAYER met3 ;
        RECT 0.000 253.000 0.600 253.600 ;
    END
  END Tile_X0Y0_W2BEG[0]
  PIN Tile_X0Y0_W2BEG[1]
    DIRECTION OUTPUT ;
    USE SIGNAL ;
    ANTENNADIFFAREA 0.702900 ;
    PORT
      LAYER met3 ;
        RECT 0.000 254.360 0.600 254.960 ;
    END
  END Tile_X0Y0_W2BEG[1]
  PIN Tile_X0Y0_W2BEG[2]
    DIRECTION OUTPUT ;
    USE SIGNAL ;
    ANTENNADIFFAREA 0.702900 ;
    PORT
      LAYER met3 ;
        RECT 0.000 255.720 0.600 256.320 ;
    END
  END Tile_X0Y0_W2BEG[2]
  PIN Tile_X0Y0_W2BEG[3]
    DIRECTION OUTPUT ;
    USE SIGNAL ;
    ANTENNADIFFAREA 0.702900 ;
    PORT
      LAYER met3 ;
        RECT 0.000 257.080 0.600 257.680 ;
    END
  END Tile_X0Y0_W2BEG[3]
  PIN Tile_X0Y0_W2BEG[4]
    DIRECTION OUTPUT ;
    USE SIGNAL ;
    ANTENNADIFFAREA 0.702900 ;
    PORT
      LAYER met3 ;
        RECT 0.000 258.440 0.600 259.040 ;
    END
  END Tile_X0Y0_W2BEG[4]
  PIN Tile_X0Y0_W2BEG[5]
    DIRECTION OUTPUT ;
    USE SIGNAL ;
    ANTENNADIFFAREA 0.702900 ;
    PORT
      LAYER met3 ;
        RECT 0.000 259.800 0.600 260.400 ;
    END
  END Tile_X0Y0_W2BEG[5]
  PIN Tile_X0Y0_W2BEG[6]
    DIRECTION OUTPUT ;
    USE SIGNAL ;
    ANTENNADIFFAREA 0.702900 ;
    PORT
      LAYER met3 ;
        RECT 0.000 261.160 0.600 261.760 ;
    END
  END Tile_X0Y0_W2BEG[6]
  PIN Tile_X0Y0_W2BEG[7]
    DIRECTION OUTPUT ;
    USE SIGNAL ;
    ANTENNADIFFAREA 0.702900 ;
    PORT
      LAYER met3 ;
        RECT 0.000 262.520 0.600 263.120 ;
    END
  END Tile_X0Y0_W2BEG[7]
  PIN Tile_X0Y0_W2BEGb[0]
    DIRECTION OUTPUT ;
    USE SIGNAL ;
    ANTENNADIFFAREA 0.702900 ;
    PORT
      LAYER met3 ;
        RECT 0.000 263.880 0.600 264.480 ;
    END
  END Tile_X0Y0_W2BEGb[0]
  PIN Tile_X0Y0_W2BEGb[1]
    DIRECTION OUTPUT ;
    USE SIGNAL ;
    ANTENNADIFFAREA 0.702900 ;
    PORT
      LAYER met3 ;
        RECT 0.000 265.240 0.600 265.840 ;
    END
  END Tile_X0Y0_W2BEGb[1]
  PIN Tile_X0Y0_W2BEGb[2]
    DIRECTION OUTPUT ;
    USE SIGNAL ;
    ANTENNADIFFAREA 0.702900 ;
    PORT
      LAYER met3 ;
        RECT 0.000 266.600 0.600 267.200 ;
    END
  END Tile_X0Y0_W2BEGb[2]
  PIN Tile_X0Y0_W2BEGb[3]
    DIRECTION OUTPUT ;
    USE SIGNAL ;
    ANTENNADIFFAREA 0.702900 ;
    PORT
      LAYER met3 ;
        RECT 0.000 267.960 0.600 268.560 ;
    END
  END Tile_X0Y0_W2BEGb[3]
  PIN Tile_X0Y0_W2BEGb[4]
    DIRECTION OUTPUT ;
    USE SIGNAL ;
    ANTENNADIFFAREA 0.702900 ;
    PORT
      LAYER met3 ;
        RECT 0.000 269.320 0.600 269.920 ;
    END
  END Tile_X0Y0_W2BEGb[4]
  PIN Tile_X0Y0_W2BEGb[5]
    DIRECTION OUTPUT ;
    USE SIGNAL ;
    ANTENNADIFFAREA 0.702900 ;
    PORT
      LAYER met3 ;
        RECT 0.000 270.680 0.600 271.280 ;
    END
  END Tile_X0Y0_W2BEGb[5]
  PIN Tile_X0Y0_W2BEGb[6]
    DIRECTION OUTPUT ;
    USE SIGNAL ;
    ANTENNADIFFAREA 0.702900 ;
    PORT
      LAYER met3 ;
        RECT 0.000 272.040 0.600 272.640 ;
    END
  END Tile_X0Y0_W2BEGb[6]
  PIN Tile_X0Y0_W2BEGb[7]
    DIRECTION OUTPUT ;
    USE SIGNAL ;
    ANTENNADIFFAREA 0.702900 ;
    PORT
      LAYER met3 ;
        RECT 0.000 273.400 0.600 274.000 ;
    END
  END Tile_X0Y0_W2BEGb[7]
  PIN Tile_X0Y0_W6BEG[0]
    DIRECTION OUTPUT ;
    USE SIGNAL ;
    ANTENNADIFFAREA 0.702900 ;
    PORT
      LAYER met3 ;
        RECT 0.000 296.520 0.600 297.120 ;
    END
  END Tile_X0Y0_W6BEG[0]
  PIN Tile_X0Y0_W6BEG[10]
    DIRECTION OUTPUT ;
    USE SIGNAL ;
    ANTENNADIFFAREA 0.702900 ;
    PORT
      LAYER met3 ;
        RECT 0.000 310.120 0.600 310.720 ;
    END
  END Tile_X0Y0_W6BEG[10]
  PIN Tile_X0Y0_W6BEG[11]
    DIRECTION OUTPUT ;
    USE SIGNAL ;
    ANTENNADIFFAREA 0.702900 ;
    PORT
      LAYER met3 ;
        RECT 0.000 311.480 0.600 312.080 ;
    END
  END Tile_X0Y0_W6BEG[11]
  PIN Tile_X0Y0_W6BEG[1]
    DIRECTION OUTPUT ;
    USE SIGNAL ;
    ANTENNADIFFAREA 0.702900 ;
    PORT
      LAYER met3 ;
        RECT 0.000 297.880 0.600 298.480 ;
    END
  END Tile_X0Y0_W6BEG[1]
  PIN Tile_X0Y0_W6BEG[2]
    DIRECTION OUTPUT ;
    USE SIGNAL ;
    ANTENNADIFFAREA 0.702900 ;
    PORT
      LAYER met3 ;
        RECT 0.000 299.240 0.600 299.840 ;
    END
  END Tile_X0Y0_W6BEG[2]
  PIN Tile_X0Y0_W6BEG[3]
    DIRECTION OUTPUT ;
    USE SIGNAL ;
    ANTENNADIFFAREA 0.702900 ;
    PORT
      LAYER met3 ;
        RECT 0.000 300.600 0.600 301.200 ;
    END
  END Tile_X0Y0_W6BEG[3]
  PIN Tile_X0Y0_W6BEG[4]
    DIRECTION OUTPUT ;
    USE SIGNAL ;
    ANTENNADIFFAREA 0.702900 ;
    PORT
      LAYER met3 ;
        RECT 0.000 301.960 0.600 302.560 ;
    END
  END Tile_X0Y0_W6BEG[4]
  PIN Tile_X0Y0_W6BEG[5]
    DIRECTION OUTPUT ;
    USE SIGNAL ;
    ANTENNADIFFAREA 0.702900 ;
    PORT
      LAYER met3 ;
        RECT 0.000 303.320 0.600 303.920 ;
    END
  END Tile_X0Y0_W6BEG[5]
  PIN Tile_X0Y0_W6BEG[6]
    DIRECTION OUTPUT ;
    USE SIGNAL ;
    ANTENNADIFFAREA 0.702900 ;
    PORT
      LAYER met3 ;
        RECT 0.000 304.680 0.600 305.280 ;
    END
  END Tile_X0Y0_W6BEG[6]
  PIN Tile_X0Y0_W6BEG[7]
    DIRECTION OUTPUT ;
    USE SIGNAL ;
    ANTENNADIFFAREA 0.702900 ;
    PORT
      LAYER met3 ;
        RECT 0.000 306.040 0.600 306.640 ;
    END
  END Tile_X0Y0_W6BEG[7]
  PIN Tile_X0Y0_W6BEG[8]
    DIRECTION OUTPUT ;
    USE SIGNAL ;
    ANTENNADIFFAREA 0.702900 ;
    PORT
      LAYER met3 ;
        RECT 0.000 307.400 0.600 308.000 ;
    END
  END Tile_X0Y0_W6BEG[8]
  PIN Tile_X0Y0_W6BEG[9]
    DIRECTION OUTPUT ;
    USE SIGNAL ;
    ANTENNADIFFAREA 0.702900 ;
    PORT
      LAYER met3 ;
        RECT 0.000 308.760 0.600 309.360 ;
    END
  END Tile_X0Y0_W6BEG[9]
  PIN Tile_X0Y0_WW4BEG[0]
    DIRECTION OUTPUT ;
    USE SIGNAL ;
    ANTENNADIFFAREA 0.702900 ;
    PORT
      LAYER met3 ;
        RECT 0.000 274.760 0.600 275.360 ;
    END
  END Tile_X0Y0_WW4BEG[0]
  PIN Tile_X0Y0_WW4BEG[10]
    DIRECTION OUTPUT ;
    USE SIGNAL ;
    ANTENNADIFFAREA 0.702900 ;
    PORT
      LAYER met3 ;
        RECT 0.000 288.360 0.600 288.960 ;
    END
  END Tile_X0Y0_WW4BEG[10]
  PIN Tile_X0Y0_WW4BEG[11]
    DIRECTION OUTPUT ;
    USE SIGNAL ;
    ANTENNADIFFAREA 0.702900 ;
    PORT
      LAYER met3 ;
        RECT 0.000 289.720 0.600 290.320 ;
    END
  END Tile_X0Y0_WW4BEG[11]
  PIN Tile_X0Y0_WW4BEG[12]
    DIRECTION OUTPUT ;
    USE SIGNAL ;
    ANTENNADIFFAREA 0.702900 ;
    PORT
      LAYER met3 ;
        RECT 0.000 291.080 0.600 291.680 ;
    END
  END Tile_X0Y0_WW4BEG[12]
  PIN Tile_X0Y0_WW4BEG[13]
    DIRECTION OUTPUT ;
    USE SIGNAL ;
    ANTENNADIFFAREA 0.702900 ;
    PORT
      LAYER met3 ;
        RECT 0.000 292.440 0.600 293.040 ;
    END
  END Tile_X0Y0_WW4BEG[13]
  PIN Tile_X0Y0_WW4BEG[14]
    DIRECTION OUTPUT ;
    USE SIGNAL ;
    ANTENNADIFFAREA 0.702900 ;
    PORT
      LAYER met3 ;
        RECT 0.000 293.800 0.600 294.400 ;
    END
  END Tile_X0Y0_WW4BEG[14]
  PIN Tile_X0Y0_WW4BEG[15]
    DIRECTION OUTPUT ;
    USE SIGNAL ;
    ANTENNADIFFAREA 0.702900 ;
    PORT
      LAYER met3 ;
        RECT 0.000 295.160 0.600 295.760 ;
    END
  END Tile_X0Y0_WW4BEG[15]
  PIN Tile_X0Y0_WW4BEG[1]
    DIRECTION OUTPUT ;
    USE SIGNAL ;
    ANTENNADIFFAREA 0.702900 ;
    PORT
      LAYER met3 ;
        RECT 0.000 276.120 0.600 276.720 ;
    END
  END Tile_X0Y0_WW4BEG[1]
  PIN Tile_X0Y0_WW4BEG[2]
    DIRECTION OUTPUT ;
    USE SIGNAL ;
    ANTENNADIFFAREA 0.702900 ;
    PORT
      LAYER met3 ;
        RECT 0.000 277.480 0.600 278.080 ;
    END
  END Tile_X0Y0_WW4BEG[2]
  PIN Tile_X0Y0_WW4BEG[3]
    DIRECTION OUTPUT ;
    USE SIGNAL ;
    ANTENNADIFFAREA 0.702900 ;
    PORT
      LAYER met3 ;
        RECT 0.000 278.840 0.600 279.440 ;
    END
  END Tile_X0Y0_WW4BEG[3]
  PIN Tile_X0Y0_WW4BEG[4]
    DIRECTION OUTPUT ;
    USE SIGNAL ;
    ANTENNADIFFAREA 0.702900 ;
    PORT
      LAYER met3 ;
        RECT 0.000 280.200 0.600 280.800 ;
    END
  END Tile_X0Y0_WW4BEG[4]
  PIN Tile_X0Y0_WW4BEG[5]
    DIRECTION OUTPUT ;
    USE SIGNAL ;
    ANTENNADIFFAREA 0.702900 ;
    PORT
      LAYER met3 ;
        RECT 0.000 281.560 0.600 282.160 ;
    END
  END Tile_X0Y0_WW4BEG[5]
  PIN Tile_X0Y0_WW4BEG[6]
    DIRECTION OUTPUT ;
    USE SIGNAL ;
    ANTENNADIFFAREA 0.702900 ;
    PORT
      LAYER met3 ;
        RECT 0.000 282.920 0.600 283.520 ;
    END
  END Tile_X0Y0_WW4BEG[6]
  PIN Tile_X0Y0_WW4BEG[7]
    DIRECTION OUTPUT ;
    USE SIGNAL ;
    ANTENNADIFFAREA 0.702900 ;
    PORT
      LAYER met3 ;
        RECT 0.000 284.280 0.600 284.880 ;
    END
  END Tile_X0Y0_WW4BEG[7]
  PIN Tile_X0Y0_WW4BEG[8]
    DIRECTION OUTPUT ;
    USE SIGNAL ;
    ANTENNADIFFAREA 0.702900 ;
    PORT
      LAYER met3 ;
        RECT 0.000 285.640 0.600 286.240 ;
    END
  END Tile_X0Y0_WW4BEG[8]
  PIN Tile_X0Y0_WW4BEG[9]
    DIRECTION OUTPUT ;
    USE SIGNAL ;
    ANTENNADIFFAREA 0.702900 ;
    PORT
      LAYER met3 ;
        RECT 0.000 287.000 0.600 287.600 ;
    END
  END Tile_X0Y0_WW4BEG[9]
  PIN Tile_X0Y1_E1END[0]
    DIRECTION INPUT ;
    USE SIGNAL ;
    ANTENNAGATEAREA 1.289700 ;
    ANTENNADIFFAREA 0.434700 ;
    PORT
      LAYER met3 ;
        RECT 0.000 89.800 0.600 90.400 ;
    END
  END Tile_X0Y1_E1END[0]
  PIN Tile_X0Y1_E1END[1]
    DIRECTION INPUT ;
    USE SIGNAL ;
    ANTENNAGATEAREA 0.570000 ;
    PORT
      LAYER met3 ;
        RECT 0.000 91.160 0.600 91.760 ;
    END
  END Tile_X0Y1_E1END[1]
  PIN Tile_X0Y1_E1END[2]
    DIRECTION INPUT ;
    USE SIGNAL ;
    ANTENNAGATEAREA 1.004700 ;
    ANTENNADIFFAREA 0.434700 ;
    PORT
      LAYER met3 ;
        RECT 0.000 92.520 0.600 93.120 ;
    END
  END Tile_X0Y1_E1END[2]
  PIN Tile_X0Y1_E1END[3]
    DIRECTION INPUT ;
    USE SIGNAL ;
    ANTENNAGATEAREA 0.729000 ;
    PORT
      LAYER met3 ;
        RECT 0.000 93.880 0.600 94.480 ;
    END
  END Tile_X0Y1_E1END[3]
  PIN Tile_X0Y1_E2END[0]
    DIRECTION INPUT ;
    USE SIGNAL ;
    ANTENNAGATEAREA 1.308000 ;
    PORT
      LAYER met3 ;
        RECT 0.000 106.120 0.600 106.720 ;
    END
  END Tile_X0Y1_E2END[0]
  PIN Tile_X0Y1_E2END[1]
    DIRECTION INPUT ;
    USE SIGNAL ;
    ANTENNAGATEAREA 1.308000 ;
    PORT
      LAYER met3 ;
        RECT 0.000 107.480 0.600 108.080 ;
    END
  END Tile_X0Y1_E2END[1]
  PIN Tile_X0Y1_E2END[2]
    DIRECTION INPUT ;
    USE SIGNAL ;
    ANTENNAGATEAREA 1.434000 ;
    PORT
      LAYER met3 ;
        RECT 0.000 108.840 0.600 109.440 ;
    END
  END Tile_X0Y1_E2END[2]
  PIN Tile_X0Y1_E2END[3]
    DIRECTION INPUT ;
    USE SIGNAL ;
    ANTENNAGATEAREA 1.308000 ;
    PORT
      LAYER met3 ;
        RECT 0.000 110.200 0.600 110.800 ;
    END
  END Tile_X0Y1_E2END[3]
  PIN Tile_X0Y1_E2END[4]
    DIRECTION INPUT ;
    USE SIGNAL ;
    ANTENNAGATEAREA 1.396500 ;
    PORT
      LAYER met3 ;
        RECT 0.000 111.560 0.600 112.160 ;
    END
  END Tile_X0Y1_E2END[4]
  PIN Tile_X0Y1_E2END[5]
    DIRECTION INPUT ;
    USE SIGNAL ;
    ANTENNAGATEAREA 1.522500 ;
    PORT
      LAYER met3 ;
        RECT 0.000 112.920 0.600 113.520 ;
    END
  END Tile_X0Y1_E2END[5]
  PIN Tile_X0Y1_E2END[6]
    DIRECTION INPUT ;
    USE SIGNAL ;
    ANTENNAGATEAREA 0.901500 ;
    PORT
      LAYER met3 ;
        RECT 0.000 114.280 0.600 114.880 ;
    END
  END Tile_X0Y1_E2END[6]
  PIN Tile_X0Y1_E2END[7]
    DIRECTION INPUT ;
    USE SIGNAL ;
    ANTENNAGATEAREA 0.901500 ;
    PORT
      LAYER met3 ;
        RECT 0.000 115.640 0.600 116.240 ;
    END
  END Tile_X0Y1_E2END[7]
  PIN Tile_X0Y1_E2MID[0]
    DIRECTION INPUT ;
    USE SIGNAL ;
    ANTENNAGATEAREA 0.126000 ;
    PORT
      LAYER met3 ;
        RECT 0.000 95.240 0.600 95.840 ;
    END
  END Tile_X0Y1_E2MID[0]
  PIN Tile_X0Y1_E2MID[1]
    DIRECTION INPUT ;
    USE SIGNAL ;
    ANTENNAGATEAREA 0.126000 ;
    PORT
      LAYER met3 ;
        RECT 0.000 96.600 0.600 97.200 ;
    END
  END Tile_X0Y1_E2MID[1]
  PIN Tile_X0Y1_E2MID[2]
    DIRECTION INPUT ;
    USE SIGNAL ;
    ANTENNAGATEAREA 1.280400 ;
    ANTENNADIFFAREA 0.869400 ;
    PORT
      LAYER met3 ;
        RECT 0.000 97.960 0.600 98.560 ;
    END
  END Tile_X0Y1_E2MID[2]
  PIN Tile_X0Y1_E2MID[3]
    DIRECTION INPUT ;
    USE SIGNAL ;
    ANTENNAGATEAREA 0.126000 ;
    PORT
      LAYER met3 ;
        RECT 0.000 99.320 0.600 99.920 ;
    END
  END Tile_X0Y1_E2MID[3]
  PIN Tile_X0Y1_E2MID[4]
    DIRECTION INPUT ;
    USE SIGNAL ;
    ANTENNAGATEAREA 0.126000 ;
    PORT
      LAYER met3 ;
        RECT 0.000 100.680 0.600 101.280 ;
    END
  END Tile_X0Y1_E2MID[4]
  PIN Tile_X0Y1_E2MID[5]
    DIRECTION INPUT ;
    USE SIGNAL ;
    ANTENNAGATEAREA 0.560700 ;
    ANTENNADIFFAREA 0.434700 ;
    PORT
      LAYER met3 ;
        RECT 0.000 102.040 0.600 102.640 ;
    END
  END Tile_X0Y1_E2MID[5]
  PIN Tile_X0Y1_E2MID[6]
    DIRECTION INPUT ;
    USE SIGNAL ;
    ANTENNAGATEAREA 1.214700 ;
    ANTENNADIFFAREA 0.434700 ;
    PORT
      LAYER met3 ;
        RECT 0.000 103.400 0.600 104.000 ;
    END
  END Tile_X0Y1_E2MID[6]
  PIN Tile_X0Y1_E2MID[7]
    DIRECTION INPUT ;
    USE SIGNAL ;
    ANTENNAGATEAREA 0.560700 ;
    ANTENNADIFFAREA 0.434700 ;
    PORT
      LAYER met3 ;
        RECT 0.000 104.760 0.600 105.360 ;
    END
  END Tile_X0Y1_E2MID[7]
  PIN Tile_X0Y1_E6END[0]
    DIRECTION INPUT ;
    USE SIGNAL ;
    ANTENNAGATEAREA 1.097700 ;
    ANTENNADIFFAREA 0.434700 ;
    PORT
      LAYER met3 ;
        RECT 0.000 138.760 0.600 139.360 ;
    END
  END Tile_X0Y1_E6END[0]
  PIN Tile_X0Y1_E6END[10]
    DIRECTION INPUT ;
    USE SIGNAL ;
    PORT
      LAYER met3 ;
        RECT 0.000 152.360 0.600 152.960 ;
    END
  END Tile_X0Y1_E6END[10]
  PIN Tile_X0Y1_E6END[11]
    DIRECTION INPUT ;
    USE SIGNAL ;
    ANTENNAGATEAREA 0.285000 ;
    PORT
      LAYER met3 ;
        RECT 0.000 153.720 0.600 154.320 ;
    END
  END Tile_X0Y1_E6END[11]
  PIN Tile_X0Y1_E6END[1]
    DIRECTION INPUT ;
    USE SIGNAL ;
    ANTENNAGATEAREA 0.378000 ;
    PORT
      LAYER met3 ;
        RECT 0.000 140.120 0.600 140.720 ;
    END
  END Tile_X0Y1_E6END[1]
  PIN Tile_X0Y1_E6END[2]
    DIRECTION INPUT ;
    USE SIGNAL ;
    ANTENNAGATEAREA 0.630000 ;
    PORT
      LAYER met3 ;
        RECT 0.000 141.480 0.600 142.080 ;
    END
  END Tile_X0Y1_E6END[2]
  PIN Tile_X0Y1_E6END[3]
    DIRECTION INPUT ;
    USE SIGNAL ;
    ANTENNAGATEAREA 0.625500 ;
    PORT
      LAYER met3 ;
        RECT 0.000 142.840 0.600 143.440 ;
    END
  END Tile_X0Y1_E6END[3]
  PIN Tile_X0Y1_E6END[4]
    DIRECTION INPUT ;
    USE SIGNAL ;
    ANTENNAGATEAREA 0.537000 ;
    PORT
      LAYER met3 ;
        RECT 0.000 144.200 0.600 144.800 ;
    END
  END Tile_X0Y1_E6END[4]
  PIN Tile_X0Y1_E6END[5]
    DIRECTION INPUT ;
    USE SIGNAL ;
    ANTENNAGATEAREA 0.686700 ;
    ANTENNADIFFAREA 0.434700 ;
    PORT
      LAYER met3 ;
        RECT 0.000 145.560 0.600 146.160 ;
    END
  END Tile_X0Y1_E6END[5]
  PIN Tile_X0Y1_E6END[6]
    DIRECTION INPUT ;
    USE SIGNAL ;
    ANTENNAGATEAREA 1.247400 ;
    ANTENNADIFFAREA 0.869400 ;
    PORT
      LAYER met3 ;
        RECT 0.000 146.920 0.600 147.520 ;
    END
  END Tile_X0Y1_E6END[6]
  PIN Tile_X0Y1_E6END[7]
    DIRECTION INPUT ;
    USE SIGNAL ;
    ANTENNAGATEAREA 0.378000 ;
    PORT
      LAYER met3 ;
        RECT 0.000 148.280 0.600 148.880 ;
    END
  END Tile_X0Y1_E6END[7]
  PIN Tile_X0Y1_E6END[8]
    DIRECTION INPUT ;
    USE SIGNAL ;
    ANTENNAGATEAREA 0.411000 ;
    PORT
      LAYER met3 ;
        RECT 0.000 149.640 0.600 150.240 ;
    END
  END Tile_X0Y1_E6END[8]
  PIN Tile_X0Y1_E6END[9]
    DIRECTION INPUT ;
    USE SIGNAL ;
    ANTENNAGATEAREA 0.126000 ;
    PORT
      LAYER met3 ;
        RECT 0.000 151.000 0.600 151.600 ;
    END
  END Tile_X0Y1_E6END[9]
  PIN Tile_X0Y1_EE4END[0]
    DIRECTION INPUT ;
    USE SIGNAL ;
    ANTENNAGATEAREA 0.663000 ;
    PORT
      LAYER met3 ;
        RECT 0.000 117.000 0.600 117.600 ;
    END
  END Tile_X0Y1_EE4END[0]
  PIN Tile_X0Y1_EE4END[10]
    DIRECTION INPUT ;
    USE SIGNAL ;
    ANTENNAGATEAREA 0.906000 ;
    PORT
      LAYER met3 ;
        RECT 0.000 130.600 0.600 131.200 ;
    END
  END Tile_X0Y1_EE4END[10]
  PIN Tile_X0Y1_EE4END[11]
    DIRECTION INPUT ;
    USE SIGNAL ;
    ANTENNAGATEAREA 1.340700 ;
    ANTENNADIFFAREA 0.434700 ;
    PORT
      LAYER met3 ;
        RECT 0.000 131.960 0.600 132.560 ;
    END
  END Tile_X0Y1_EE4END[11]
  PIN Tile_X0Y1_EE4END[12]
    DIRECTION INPUT ;
    USE SIGNAL ;
    ANTENNAGATEAREA 1.340700 ;
    ANTENNADIFFAREA 0.434700 ;
    PORT
      LAYER met3 ;
        RECT 0.000 133.320 0.600 133.920 ;
    END
  END Tile_X0Y1_EE4END[12]
  PIN Tile_X0Y1_EE4END[13]
    DIRECTION INPUT ;
    USE SIGNAL ;
    ANTENNAGATEAREA 0.906000 ;
    PORT
      LAYER met3 ;
        RECT 0.000 134.680 0.600 135.280 ;
    END
  END Tile_X0Y1_EE4END[13]
  PIN Tile_X0Y1_EE4END[14]
    DIRECTION INPUT ;
    USE SIGNAL ;
    ANTENNAGATEAREA 0.906000 ;
    PORT
      LAYER met3 ;
        RECT 0.000 136.040 0.600 136.640 ;
    END
  END Tile_X0Y1_EE4END[14]
  PIN Tile_X0Y1_EE4END[15]
    DIRECTION INPUT ;
    USE SIGNAL ;
    ANTENNAGATEAREA 0.906000 ;
    PORT
      LAYER met3 ;
        RECT 0.000 137.400 0.600 138.000 ;
    END
  END Tile_X0Y1_EE4END[15]
  PIN Tile_X0Y1_EE4END[1]
    DIRECTION INPUT ;
    USE SIGNAL ;
    ANTENNAGATEAREA 0.663000 ;
    PORT
      LAYER met3 ;
        RECT 0.000 118.360 0.600 118.960 ;
    END
  END Tile_X0Y1_EE4END[1]
  PIN Tile_X0Y1_EE4END[2]
    DIRECTION INPUT ;
    USE SIGNAL ;
    ANTENNAGATEAREA 0.663000 ;
    PORT
      LAYER met3 ;
        RECT 0.000 119.720 0.600 120.320 ;
    END
  END Tile_X0Y1_EE4END[2]
  PIN Tile_X0Y1_EE4END[3]
    DIRECTION INPUT ;
    USE SIGNAL ;
    ANTENNAGATEAREA 0.663000 ;
    PORT
      LAYER met3 ;
        RECT 0.000 121.080 0.600 121.680 ;
    END
  END Tile_X0Y1_EE4END[3]
  PIN Tile_X0Y1_EE4END[4]
    DIRECTION INPUT ;
    USE SIGNAL ;
    ANTENNAGATEAREA 0.537000 ;
    PORT
      LAYER met3 ;
        RECT 0.000 122.440 0.600 123.040 ;
    END
  END Tile_X0Y1_EE4END[4]
  PIN Tile_X0Y1_EE4END[5]
    DIRECTION INPUT ;
    USE SIGNAL ;
    ANTENNAGATEAREA 1.032000 ;
    PORT
      LAYER met3 ;
        RECT 0.000 123.800 0.600 124.400 ;
    END
  END Tile_X0Y1_EE4END[5]
  PIN Tile_X0Y1_EE4END[6]
    DIRECTION INPUT ;
    USE SIGNAL ;
    ANTENNAGATEAREA 0.971700 ;
    ANTENNADIFFAREA 0.434700 ;
    PORT
      LAYER met3 ;
        RECT 0.000 125.160 0.600 125.760 ;
    END
  END Tile_X0Y1_EE4END[6]
  PIN Tile_X0Y1_EE4END[7]
    DIRECTION INPUT ;
    USE SIGNAL ;
    ANTENNAGATEAREA 0.537000 ;
    PORT
      LAYER met3 ;
        RECT 0.000 126.520 0.600 127.120 ;
    END
  END Tile_X0Y1_EE4END[7]
  PIN Tile_X0Y1_EE4END[8]
    DIRECTION INPUT ;
    USE SIGNAL ;
    ANTENNAGATEAREA 0.906000 ;
    PORT
      LAYER met3 ;
        RECT 0.000 127.880 0.600 128.480 ;
    END
  END Tile_X0Y1_EE4END[8]
  PIN Tile_X0Y1_EE4END[9]
    DIRECTION INPUT ;
    USE SIGNAL ;
    ANTENNAGATEAREA 0.906000 ;
    PORT
      LAYER met3 ;
        RECT 0.000 129.240 0.600 129.840 ;
    END
  END Tile_X0Y1_EE4END[9]
  PIN Tile_X0Y1_FrameData[0]
    DIRECTION INPUT ;
    USE SIGNAL ;
    ANTENNAGATEAREA 0.795000 ;
    PORT
      LAYER met3 ;
        RECT 0.000 155.080 0.600 155.680 ;
    END
  END Tile_X0Y1_FrameData[0]
  PIN Tile_X0Y1_FrameData[10]
    DIRECTION INPUT ;
    USE SIGNAL ;
    ANTENNAGATEAREA 0.795000 ;
    PORT
      LAYER met3 ;
        RECT 0.000 168.680 0.600 169.280 ;
    END
  END Tile_X0Y1_FrameData[10]
  PIN Tile_X0Y1_FrameData[11]
    DIRECTION INPUT ;
    USE SIGNAL ;
    ANTENNAGATEAREA 0.795000 ;
    PORT
      LAYER met3 ;
        RECT 0.000 170.040 0.600 170.640 ;
    END
  END Tile_X0Y1_FrameData[11]
  PIN Tile_X0Y1_FrameData[12]
    DIRECTION INPUT ;
    USE SIGNAL ;
    ANTENNAGATEAREA 0.795000 ;
    PORT
      LAYER met3 ;
        RECT 0.000 171.400 0.600 172.000 ;
    END
  END Tile_X0Y1_FrameData[12]
  PIN Tile_X0Y1_FrameData[13]
    DIRECTION INPUT ;
    USE SIGNAL ;
    ANTENNAGATEAREA 0.795000 ;
    PORT
      LAYER met3 ;
        RECT 0.000 172.760 0.600 173.360 ;
    END
  END Tile_X0Y1_FrameData[13]
  PIN Tile_X0Y1_FrameData[14]
    DIRECTION INPUT ;
    USE SIGNAL ;
    ANTENNAGATEAREA 0.795000 ;
    PORT
      LAYER met3 ;
        RECT 0.000 174.120 0.600 174.720 ;
    END
  END Tile_X0Y1_FrameData[14]
  PIN Tile_X0Y1_FrameData[15]
    DIRECTION INPUT ;
    USE SIGNAL ;
    ANTENNAGATEAREA 1.229700 ;
    ANTENNADIFFAREA 0.434700 ;
    PORT
      LAYER met3 ;
        RECT 0.000 175.480 0.600 176.080 ;
    END
  END Tile_X0Y1_FrameData[15]
  PIN Tile_X0Y1_FrameData[16]
    DIRECTION INPUT ;
    USE SIGNAL ;
    ANTENNAGATEAREA 0.795000 ;
    PORT
      LAYER met3 ;
        RECT 0.000 176.840 0.600 177.440 ;
    END
  END Tile_X0Y1_FrameData[16]
  PIN Tile_X0Y1_FrameData[17]
    DIRECTION INPUT ;
    USE SIGNAL ;
    ANTENNAGATEAREA 0.795000 ;
    PORT
      LAYER met3 ;
        RECT 0.000 178.200 0.600 178.800 ;
    END
  END Tile_X0Y1_FrameData[17]
  PIN Tile_X0Y1_FrameData[18]
    DIRECTION INPUT ;
    USE SIGNAL ;
    ANTENNAGATEAREA 0.795000 ;
    PORT
      LAYER met3 ;
        RECT 0.000 179.560 0.600 180.160 ;
    END
  END Tile_X0Y1_FrameData[18]
  PIN Tile_X0Y1_FrameData[19]
    DIRECTION INPUT ;
    USE SIGNAL ;
    ANTENNAGATEAREA 0.795000 ;
    PORT
      LAYER met3 ;
        RECT 0.000 180.920 0.600 181.520 ;
    END
  END Tile_X0Y1_FrameData[19]
  PIN Tile_X0Y1_FrameData[1]
    DIRECTION INPUT ;
    USE SIGNAL ;
    ANTENNAGATEAREA 0.795000 ;
    PORT
      LAYER met3 ;
        RECT 0.000 156.440 0.600 157.040 ;
    END
  END Tile_X0Y1_FrameData[1]
  PIN Tile_X0Y1_FrameData[20]
    DIRECTION INPUT ;
    USE SIGNAL ;
    ANTENNAGATEAREA 0.795000 ;
    PORT
      LAYER met3 ;
        RECT 0.000 182.280 0.600 182.880 ;
    END
  END Tile_X0Y1_FrameData[20]
  PIN Tile_X0Y1_FrameData[21]
    DIRECTION INPUT ;
    USE SIGNAL ;
    ANTENNAGATEAREA 0.795000 ;
    PORT
      LAYER met3 ;
        RECT 0.000 183.640 0.600 184.240 ;
    END
  END Tile_X0Y1_FrameData[21]
  PIN Tile_X0Y1_FrameData[22]
    DIRECTION INPUT ;
    USE SIGNAL ;
    ANTENNAGATEAREA 0.795000 ;
    PORT
      LAYER met3 ;
        RECT 0.000 185.000 0.600 185.600 ;
    END
  END Tile_X0Y1_FrameData[22]
  PIN Tile_X0Y1_FrameData[23]
    DIRECTION INPUT ;
    USE SIGNAL ;
    ANTENNAGATEAREA 0.795000 ;
    PORT
      LAYER met3 ;
        RECT 0.000 186.360 0.600 186.960 ;
    END
  END Tile_X0Y1_FrameData[23]
  PIN Tile_X0Y1_FrameData[24]
    DIRECTION INPUT ;
    USE SIGNAL ;
    ANTENNAGATEAREA 1.229700 ;
    ANTENNADIFFAREA 0.434700 ;
    PORT
      LAYER met3 ;
        RECT 0.000 187.720 0.600 188.320 ;
    END
  END Tile_X0Y1_FrameData[24]
  PIN Tile_X0Y1_FrameData[25]
    DIRECTION INPUT ;
    USE SIGNAL ;
    ANTENNAGATEAREA 0.795000 ;
    PORT
      LAYER met3 ;
        RECT 0.000 189.080 0.600 189.680 ;
    END
  END Tile_X0Y1_FrameData[25]
  PIN Tile_X0Y1_FrameData[26]
    DIRECTION INPUT ;
    USE SIGNAL ;
    ANTENNAGATEAREA 0.795000 ;
    PORT
      LAYER met3 ;
        RECT 0.000 190.440 0.600 191.040 ;
    END
  END Tile_X0Y1_FrameData[26]
  PIN Tile_X0Y1_FrameData[27]
    DIRECTION INPUT ;
    USE SIGNAL ;
    ANTENNAGATEAREA 0.954000 ;
    PORT
      LAYER met3 ;
        RECT 0.000 191.800 0.600 192.400 ;
    END
  END Tile_X0Y1_FrameData[27]
  PIN Tile_X0Y1_FrameData[28]
    DIRECTION INPUT ;
    USE SIGNAL ;
    ANTENNAGATEAREA 0.954000 ;
    PORT
      LAYER met3 ;
        RECT 0.000 193.160 0.600 193.760 ;
    END
  END Tile_X0Y1_FrameData[28]
  PIN Tile_X0Y1_FrameData[29]
    DIRECTION INPUT ;
    USE SIGNAL ;
    ANTENNAGATEAREA 0.954000 ;
    PORT
      LAYER met3 ;
        RECT 0.000 194.520 0.600 195.120 ;
    END
  END Tile_X0Y1_FrameData[29]
  PIN Tile_X0Y1_FrameData[2]
    DIRECTION INPUT ;
    USE SIGNAL ;
    ANTENNAGATEAREA 0.795000 ;
    PORT
      LAYER met3 ;
        RECT 0.000 157.800 0.600 158.400 ;
    END
  END Tile_X0Y1_FrameData[2]
  PIN Tile_X0Y1_FrameData[30]
    DIRECTION INPUT ;
    USE SIGNAL ;
    ANTENNAGATEAREA 0.954000 ;
    PORT
      LAYER met3 ;
        RECT 0.000 195.880 0.600 196.480 ;
    END
  END Tile_X0Y1_FrameData[30]
  PIN Tile_X0Y1_FrameData[31]
    DIRECTION INPUT ;
    USE SIGNAL ;
    ANTENNAGATEAREA 0.954000 ;
    PORT
      LAYER met3 ;
        RECT 0.000 197.240 0.600 197.840 ;
    END
  END Tile_X0Y1_FrameData[31]
  PIN Tile_X0Y1_FrameData[3]
    DIRECTION INPUT ;
    USE SIGNAL ;
    ANTENNAGATEAREA 0.795000 ;
    PORT
      LAYER met3 ;
        RECT 0.000 159.160 0.600 159.760 ;
    END
  END Tile_X0Y1_FrameData[3]
  PIN Tile_X0Y1_FrameData[4]
    DIRECTION INPUT ;
    USE SIGNAL ;
    ANTENNAGATEAREA 1.229700 ;
    ANTENNADIFFAREA 0.434700 ;
    PORT
      LAYER met3 ;
        RECT 0.000 160.520 0.600 161.120 ;
    END
  END Tile_X0Y1_FrameData[4]
  PIN Tile_X0Y1_FrameData[5]
    DIRECTION INPUT ;
    USE SIGNAL ;
    ANTENNAGATEAREA 0.795000 ;
    PORT
      LAYER met3 ;
        RECT 0.000 161.880 0.600 162.480 ;
    END
  END Tile_X0Y1_FrameData[5]
  PIN Tile_X0Y1_FrameData[6]
    DIRECTION INPUT ;
    USE SIGNAL ;
    ANTENNAGATEAREA 0.795000 ;
    PORT
      LAYER met3 ;
        RECT 0.000 163.240 0.600 163.840 ;
    END
  END Tile_X0Y1_FrameData[6]
  PIN Tile_X0Y1_FrameData[7]
    DIRECTION INPUT ;
    USE SIGNAL ;
    ANTENNAGATEAREA 0.795000 ;
    PORT
      LAYER met3 ;
        RECT 0.000 164.600 0.600 165.200 ;
    END
  END Tile_X0Y1_FrameData[7]
  PIN Tile_X0Y1_FrameData[8]
    DIRECTION INPUT ;
    USE SIGNAL ;
    ANTENNAGATEAREA 0.795000 ;
    PORT
      LAYER met3 ;
        RECT 0.000 165.960 0.600 166.560 ;
    END
  END Tile_X0Y1_FrameData[8]
  PIN Tile_X0Y1_FrameData[9]
    DIRECTION INPUT ;
    USE SIGNAL ;
    ANTENNAGATEAREA 0.795000 ;
    PORT
      LAYER met3 ;
        RECT 0.000 167.320 0.600 167.920 ;
    END
  END Tile_X0Y1_FrameData[9]
  PIN Tile_X0Y1_FrameData_O[0]
    DIRECTION OUTPUT ;
    USE SIGNAL ;
    ANTENNADIFFAREA 0.702900 ;
    PORT
      LAYER met3 ;
        RECT 64.720 157.800 65.320 158.400 ;
    END
  END Tile_X0Y1_FrameData_O[0]
  PIN Tile_X0Y1_FrameData_O[10]
    DIRECTION OUTPUT ;
    USE SIGNAL ;
    ANTENNADIFFAREA 0.702900 ;
    PORT
      LAYER met3 ;
        RECT 64.720 198.600 65.320 199.200 ;
    END
  END Tile_X0Y1_FrameData_O[10]
  PIN Tile_X0Y1_FrameData_O[11]
    DIRECTION OUTPUT ;
    USE SIGNAL ;
    ANTENNADIFFAREA 0.702900 ;
    PORT
      LAYER met3 ;
        RECT 64.720 202.680 65.320 203.280 ;
    END
  END Tile_X0Y1_FrameData_O[11]
  PIN Tile_X0Y1_FrameData_O[12]
    DIRECTION OUTPUT ;
    USE SIGNAL ;
    ANTENNADIFFAREA 0.702900 ;
    PORT
      LAYER met3 ;
        RECT 64.720 206.760 65.320 207.360 ;
    END
  END Tile_X0Y1_FrameData_O[12]
  PIN Tile_X0Y1_FrameData_O[13]
    DIRECTION OUTPUT ;
    USE SIGNAL ;
    ANTENNADIFFAREA 0.702900 ;
    PORT
      LAYER met3 ;
        RECT 64.720 210.840 65.320 211.440 ;
    END
  END Tile_X0Y1_FrameData_O[13]
  PIN Tile_X0Y1_FrameData_O[14]
    DIRECTION OUTPUT ;
    USE SIGNAL ;
    ANTENNADIFFAREA 0.702900 ;
    PORT
      LAYER met3 ;
        RECT 64.720 214.920 65.320 215.520 ;
    END
  END Tile_X0Y1_FrameData_O[14]
  PIN Tile_X0Y1_FrameData_O[15]
    DIRECTION OUTPUT ;
    USE SIGNAL ;
    ANTENNADIFFAREA 0.702900 ;
    PORT
      LAYER met3 ;
        RECT 64.720 219.000 65.320 219.600 ;
    END
  END Tile_X0Y1_FrameData_O[15]
  PIN Tile_X0Y1_FrameData_O[16]
    DIRECTION OUTPUT ;
    USE SIGNAL ;
    ANTENNADIFFAREA 0.702900 ;
    PORT
      LAYER met3 ;
        RECT 64.720 223.080 65.320 223.680 ;
    END
  END Tile_X0Y1_FrameData_O[16]
  PIN Tile_X0Y1_FrameData_O[17]
    DIRECTION OUTPUT ;
    USE SIGNAL ;
    ANTENNADIFFAREA 0.702900 ;
    PORT
      LAYER met3 ;
        RECT 64.720 227.160 65.320 227.760 ;
    END
  END Tile_X0Y1_FrameData_O[17]
  PIN Tile_X0Y1_FrameData_O[18]
    DIRECTION OUTPUT ;
    USE SIGNAL ;
    ANTENNADIFFAREA 0.702900 ;
    PORT
      LAYER met3 ;
        RECT 64.720 231.240 65.320 231.840 ;
    END
  END Tile_X0Y1_FrameData_O[18]
  PIN Tile_X0Y1_FrameData_O[19]
    DIRECTION OUTPUT ;
    USE SIGNAL ;
    ANTENNADIFFAREA 0.702900 ;
    PORT
      LAYER met3 ;
        RECT 64.720 235.320 65.320 235.920 ;
    END
  END Tile_X0Y1_FrameData_O[19]
  PIN Tile_X0Y1_FrameData_O[1]
    DIRECTION OUTPUT ;
    USE SIGNAL ;
    ANTENNADIFFAREA 0.702900 ;
    PORT
      LAYER met3 ;
        RECT 64.720 161.880 65.320 162.480 ;
    END
  END Tile_X0Y1_FrameData_O[1]
  PIN Tile_X0Y1_FrameData_O[20]
    DIRECTION OUTPUT ;
    USE SIGNAL ;
    ANTENNADIFFAREA 0.702900 ;
    PORT
      LAYER met3 ;
        RECT 64.720 239.400 65.320 240.000 ;
    END
  END Tile_X0Y1_FrameData_O[20]
  PIN Tile_X0Y1_FrameData_O[21]
    DIRECTION OUTPUT ;
    USE SIGNAL ;
    ANTENNADIFFAREA 0.702900 ;
    PORT
      LAYER met3 ;
        RECT 64.720 243.480 65.320 244.080 ;
    END
  END Tile_X0Y1_FrameData_O[21]
  PIN Tile_X0Y1_FrameData_O[22]
    DIRECTION OUTPUT ;
    USE SIGNAL ;
    ANTENNADIFFAREA 0.702900 ;
    PORT
      LAYER met3 ;
        RECT 64.720 247.560 65.320 248.160 ;
    END
  END Tile_X0Y1_FrameData_O[22]
  PIN Tile_X0Y1_FrameData_O[23]
    DIRECTION OUTPUT ;
    USE SIGNAL ;
    ANTENNADIFFAREA 0.702900 ;
    PORT
      LAYER met3 ;
        RECT 64.720 251.640 65.320 252.240 ;
    END
  END Tile_X0Y1_FrameData_O[23]
  PIN Tile_X0Y1_FrameData_O[24]
    DIRECTION OUTPUT ;
    USE SIGNAL ;
    ANTENNADIFFAREA 0.702900 ;
    PORT
      LAYER met3 ;
        RECT 64.720 255.720 65.320 256.320 ;
    END
  END Tile_X0Y1_FrameData_O[24]
  PIN Tile_X0Y1_FrameData_O[25]
    DIRECTION OUTPUT ;
    USE SIGNAL ;
    ANTENNADIFFAREA 0.702900 ;
    PORT
      LAYER met3 ;
        RECT 64.720 259.800 65.320 260.400 ;
    END
  END Tile_X0Y1_FrameData_O[25]
  PIN Tile_X0Y1_FrameData_O[26]
    DIRECTION OUTPUT ;
    USE SIGNAL ;
    ANTENNADIFFAREA 0.702900 ;
    PORT
      LAYER met3 ;
        RECT 64.720 263.880 65.320 264.480 ;
    END
  END Tile_X0Y1_FrameData_O[26]
  PIN Tile_X0Y1_FrameData_O[27]
    DIRECTION OUTPUT ;
    USE SIGNAL ;
    ANTENNADIFFAREA 0.702900 ;
    PORT
      LAYER met3 ;
        RECT 64.720 267.960 65.320 268.560 ;
    END
  END Tile_X0Y1_FrameData_O[27]
  PIN Tile_X0Y1_FrameData_O[28]
    DIRECTION OUTPUT ;
    USE SIGNAL ;
    ANTENNADIFFAREA 0.702900 ;
    PORT
      LAYER met3 ;
        RECT 64.720 272.040 65.320 272.640 ;
    END
  END Tile_X0Y1_FrameData_O[28]
  PIN Tile_X0Y1_FrameData_O[29]
    DIRECTION OUTPUT ;
    USE SIGNAL ;
    ANTENNADIFFAREA 0.702900 ;
    PORT
      LAYER met3 ;
        RECT 64.720 276.120 65.320 276.720 ;
    END
  END Tile_X0Y1_FrameData_O[29]
  PIN Tile_X0Y1_FrameData_O[2]
    DIRECTION OUTPUT ;
    USE SIGNAL ;
    ANTENNADIFFAREA 0.702900 ;
    PORT
      LAYER met3 ;
        RECT 64.720 165.960 65.320 166.560 ;
    END
  END Tile_X0Y1_FrameData_O[2]
  PIN Tile_X0Y1_FrameData_O[30]
    DIRECTION OUTPUT ;
    USE SIGNAL ;
    ANTENNADIFFAREA 0.702900 ;
    PORT
      LAYER met3 ;
        RECT 64.720 280.200 65.320 280.800 ;
    END
  END Tile_X0Y1_FrameData_O[30]
  PIN Tile_X0Y1_FrameData_O[31]
    DIRECTION OUTPUT ;
    USE SIGNAL ;
    ANTENNADIFFAREA 0.702900 ;
    PORT
      LAYER met3 ;
        RECT 64.720 284.280 65.320 284.880 ;
    END
  END Tile_X0Y1_FrameData_O[31]
  PIN Tile_X0Y1_FrameData_O[3]
    DIRECTION OUTPUT ;
    USE SIGNAL ;
    ANTENNADIFFAREA 0.702900 ;
    PORT
      LAYER met3 ;
        RECT 64.720 170.040 65.320 170.640 ;
    END
  END Tile_X0Y1_FrameData_O[3]
  PIN Tile_X0Y1_FrameData_O[4]
    DIRECTION OUTPUT ;
    USE SIGNAL ;
    ANTENNADIFFAREA 0.702900 ;
    PORT
      LAYER met3 ;
        RECT 64.720 174.120 65.320 174.720 ;
    END
  END Tile_X0Y1_FrameData_O[4]
  PIN Tile_X0Y1_FrameData_O[5]
    DIRECTION OUTPUT ;
    USE SIGNAL ;
    ANTENNADIFFAREA 0.702900 ;
    PORT
      LAYER met3 ;
        RECT 64.720 178.200 65.320 178.800 ;
    END
  END Tile_X0Y1_FrameData_O[5]
  PIN Tile_X0Y1_FrameData_O[6]
    DIRECTION OUTPUT ;
    USE SIGNAL ;
    ANTENNADIFFAREA 0.702900 ;
    PORT
      LAYER met3 ;
        RECT 64.720 182.280 65.320 182.880 ;
    END
  END Tile_X0Y1_FrameData_O[6]
  PIN Tile_X0Y1_FrameData_O[7]
    DIRECTION OUTPUT ;
    USE SIGNAL ;
    ANTENNADIFFAREA 0.702900 ;
    PORT
      LAYER met3 ;
        RECT 64.720 186.360 65.320 186.960 ;
    END
  END Tile_X0Y1_FrameData_O[7]
  PIN Tile_X0Y1_FrameData_O[8]
    DIRECTION OUTPUT ;
    USE SIGNAL ;
    ANTENNADIFFAREA 0.702900 ;
    PORT
      LAYER met3 ;
        RECT 64.720 190.440 65.320 191.040 ;
    END
  END Tile_X0Y1_FrameData_O[8]
  PIN Tile_X0Y1_FrameData_O[9]
    DIRECTION OUTPUT ;
    USE SIGNAL ;
    ANTENNADIFFAREA 0.702900 ;
    PORT
      LAYER met3 ;
        RECT 64.720 194.520 65.320 195.120 ;
    END
  END Tile_X0Y1_FrameData_O[9]
  PIN Tile_X0Y1_FrameStrobe[0]
    DIRECTION INPUT ;
    USE SIGNAL ;
    ANTENNAGATEAREA 10.335000 ;
    PORT
      LAYER met2 ;
        RECT 15.270 0.000 15.550 0.280 ;
    END
  END Tile_X0Y1_FrameStrobe[0]
  PIN Tile_X0Y1_FrameStrobe[10]
    DIRECTION INPUT ;
    USE SIGNAL ;
    ANTENNAGATEAREA 0.159000 ;
    PORT
      LAYER met2 ;
        RECT 38.270 0.000 38.550 0.280 ;
    END
  END Tile_X0Y1_FrameStrobe[10]
  PIN Tile_X0Y1_FrameStrobe[11]
    DIRECTION INPUT ;
    USE SIGNAL ;
    ANTENNAGATEAREA 0.159000 ;
    PORT
      LAYER met2 ;
        RECT 40.570 0.000 40.850 0.280 ;
    END
  END Tile_X0Y1_FrameStrobe[11]
  PIN Tile_X0Y1_FrameStrobe[12]
    DIRECTION INPUT ;
    USE SIGNAL ;
    ANTENNAGATEAREA 0.159000 ;
    PORT
      LAYER met2 ;
        RECT 42.870 0.000 43.150 0.280 ;
    END
  END Tile_X0Y1_FrameStrobe[12]
  PIN Tile_X0Y1_FrameStrobe[13]
    DIRECTION INPUT ;
    USE SIGNAL ;
    ANTENNAGATEAREA 0.159000 ;
    PORT
      LAYER met2 ;
        RECT 45.170 0.000 45.450 0.280 ;
    END
  END Tile_X0Y1_FrameStrobe[13]
  PIN Tile_X0Y1_FrameStrobe[14]
    DIRECTION INPUT ;
    USE SIGNAL ;
    ANTENNAGATEAREA 0.159000 ;
    PORT
      LAYER met2 ;
        RECT 47.470 0.000 47.750 0.280 ;
    END
  END Tile_X0Y1_FrameStrobe[14]
  PIN Tile_X0Y1_FrameStrobe[15]
    DIRECTION INPUT ;
    USE SIGNAL ;
    ANTENNAGATEAREA 0.159000 ;
    PORT
      LAYER met2 ;
        RECT 49.770 0.000 50.050 0.280 ;
    END
  END Tile_X0Y1_FrameStrobe[15]
  PIN Tile_X0Y1_FrameStrobe[16]
    DIRECTION INPUT ;
    USE SIGNAL ;
    ANTENNAGATEAREA 0.159000 ;
    PORT
      LAYER met2 ;
        RECT 52.070 0.000 52.350 0.280 ;
    END
  END Tile_X0Y1_FrameStrobe[16]
  PIN Tile_X0Y1_FrameStrobe[17]
    DIRECTION INPUT ;
    USE SIGNAL ;
    ANTENNAGATEAREA 0.159000 ;
    PORT
      LAYER met2 ;
        RECT 54.370 0.000 54.650 0.280 ;
    END
  END Tile_X0Y1_FrameStrobe[17]
  PIN Tile_X0Y1_FrameStrobe[18]
    DIRECTION INPUT ;
    USE SIGNAL ;
    ANTENNAGATEAREA 0.159000 ;
    PORT
      LAYER met2 ;
        RECT 56.670 0.000 56.950 0.280 ;
    END
  END Tile_X0Y1_FrameStrobe[18]
  PIN Tile_X0Y1_FrameStrobe[19]
    DIRECTION INPUT ;
    USE SIGNAL ;
    ANTENNAGATEAREA 0.159000 ;
    PORT
      LAYER met2 ;
        RECT 58.970 0.000 59.250 0.280 ;
    END
  END Tile_X0Y1_FrameStrobe[19]
  PIN Tile_X0Y1_FrameStrobe[1]
    DIRECTION INPUT ;
    USE SIGNAL ;
    ANTENNAGATEAREA 10.335000 ;
    PORT
      LAYER met2 ;
        RECT 17.570 0.000 17.850 0.280 ;
    END
  END Tile_X0Y1_FrameStrobe[1]
  PIN Tile_X0Y1_FrameStrobe[2]
    DIRECTION INPUT ;
    USE SIGNAL ;
    ANTENNAGATEAREA 10.335000 ;
    PORT
      LAYER met2 ;
        RECT 19.870 0.000 20.150 0.280 ;
    END
  END Tile_X0Y1_FrameStrobe[2]
  PIN Tile_X0Y1_FrameStrobe[3]
    DIRECTION INPUT ;
    USE SIGNAL ;
    ANTENNAGATEAREA 9.698999 ;
    PORT
      LAYER met2 ;
        RECT 22.170 0.000 22.450 0.280 ;
    END
  END Tile_X0Y1_FrameStrobe[3]
  PIN Tile_X0Y1_FrameStrobe[4]
    DIRECTION INPUT ;
    USE SIGNAL ;
    ANTENNAGATEAREA 0.954000 ;
    PORT
      LAYER met2 ;
        RECT 24.470 0.000 24.750 0.280 ;
    END
  END Tile_X0Y1_FrameStrobe[4]
  PIN Tile_X0Y1_FrameStrobe[5]
    DIRECTION INPUT ;
    USE SIGNAL ;
    ANTENNAGATEAREA 2.767200 ;
    ANTENNADIFFAREA 2.608200 ;
    PORT
      LAYER met2 ;
        RECT 26.770 0.000 27.050 0.280 ;
    END
  END Tile_X0Y1_FrameStrobe[5]
  PIN Tile_X0Y1_FrameStrobe[6]
    DIRECTION INPUT ;
    USE SIGNAL ;
    ANTENNAGATEAREA 0.593700 ;
    ANTENNADIFFAREA 0.434700 ;
    PORT
      LAYER met2 ;
        RECT 29.070 0.000 29.350 0.280 ;
    END
  END Tile_X0Y1_FrameStrobe[6]
  PIN Tile_X0Y1_FrameStrobe[7]
    DIRECTION INPUT ;
    USE SIGNAL ;
    ANTENNAGATEAREA 0.593700 ;
    ANTENNADIFFAREA 0.434700 ;
    PORT
      LAYER met2 ;
        RECT 31.370 0.000 31.650 0.280 ;
    END
  END Tile_X0Y1_FrameStrobe[7]
  PIN Tile_X0Y1_FrameStrobe[8]
    DIRECTION INPUT ;
    USE SIGNAL ;
    ANTENNAGATEAREA 0.593700 ;
    ANTENNADIFFAREA 0.434700 ;
    PORT
      LAYER met2 ;
        RECT 33.670 0.000 33.950 0.280 ;
    END
  END Tile_X0Y1_FrameStrobe[8]
  PIN Tile_X0Y1_FrameStrobe[9]
    DIRECTION INPUT ;
    USE SIGNAL ;
    ANTENNAGATEAREA 3.201900 ;
    ANTENNADIFFAREA 3.042900 ;
    PORT
      LAYER met2 ;
        RECT 35.970 0.000 36.250 0.280 ;
    END
  END Tile_X0Y1_FrameStrobe[9]
  PIN Tile_X0Y1_N_GBUF_END[0]
    DIRECTION INPUT ;
    USE SIGNAL ;
    ANTENNAGATEAREA 0.852000 ;
    PORT
      LAYER met2 ;
        RECT 6.070 0.000 6.350 0.280 ;
    END
  END Tile_X0Y1_N_GBUF_END[0]
  PIN Tile_X0Y1_N_GBUF_END[1]
    DIRECTION INPUT ;
    USE SIGNAL ;
    ANTENNAGATEAREA 1.781100 ;
    ANTENNADIFFAREA 1.304100 ;
    PORT
      LAYER met2 ;
        RECT 8.370 0.000 8.650 0.280 ;
    END
  END Tile_X0Y1_N_GBUF_END[1]
  PIN Tile_X0Y1_N_GBUF_END[2]
    DIRECTION INPUT ;
    USE SIGNAL ;
    ANTENNAGATEAREA 1.781100 ;
    ANTENNADIFFAREA 1.304100 ;
    PORT
      LAYER met2 ;
        RECT 10.670 0.000 10.950 0.280 ;
    END
  END Tile_X0Y1_N_GBUF_END[2]
  PIN Tile_X0Y1_N_GBUF_END[3]
    DIRECTION INPUT ;
    USE SIGNAL ;
    ANTENNAGATEAREA 1.781100 ;
    ANTENNADIFFAREA 1.304100 ;
    PORT
      LAYER met2 ;
        RECT 12.970 0.000 13.250 0.280 ;
    END
  END Tile_X0Y1_N_GBUF_END[3]
  PIN Tile_X0Y1_W1BEG[0]
    DIRECTION OUTPUT ;
    USE SIGNAL ;
    ANTENNADIFFAREA 0.702900 ;
    PORT
      LAYER met3 ;
        RECT 0.000 24.520 0.600 25.120 ;
    END
  END Tile_X0Y1_W1BEG[0]
  PIN Tile_X0Y1_W1BEG[1]
    DIRECTION OUTPUT ;
    USE SIGNAL ;
    ANTENNADIFFAREA 0.702900 ;
    PORT
      LAYER met3 ;
        RECT 0.000 25.880 0.600 26.480 ;
    END
  END Tile_X0Y1_W1BEG[1]
  PIN Tile_X0Y1_W1BEG[2]
    DIRECTION OUTPUT ;
    USE SIGNAL ;
    ANTENNADIFFAREA 0.702900 ;
    PORT
      LAYER met3 ;
        RECT 0.000 27.240 0.600 27.840 ;
    END
  END Tile_X0Y1_W1BEG[2]
  PIN Tile_X0Y1_W1BEG[3]
    DIRECTION OUTPUT ;
    USE SIGNAL ;
    ANTENNADIFFAREA 0.702900 ;
    PORT
      LAYER met3 ;
        RECT 0.000 28.600 0.600 29.200 ;
    END
  END Tile_X0Y1_W1BEG[3]
  PIN Tile_X0Y1_W2BEG[0]
    DIRECTION OUTPUT ;
    USE SIGNAL ;
    ANTENNADIFFAREA 0.702900 ;
    PORT
      LAYER met3 ;
        RECT 0.000 29.960 0.600 30.560 ;
    END
  END Tile_X0Y1_W2BEG[0]
  PIN Tile_X0Y1_W2BEG[1]
    DIRECTION OUTPUT ;
    USE SIGNAL ;
    ANTENNADIFFAREA 0.702900 ;
    PORT
      LAYER met3 ;
        RECT 0.000 31.320 0.600 31.920 ;
    END
  END Tile_X0Y1_W2BEG[1]
  PIN Tile_X0Y1_W2BEG[2]
    DIRECTION OUTPUT ;
    USE SIGNAL ;
    ANTENNADIFFAREA 0.702900 ;
    PORT
      LAYER met3 ;
        RECT 0.000 32.680 0.600 33.280 ;
    END
  END Tile_X0Y1_W2BEG[2]
  PIN Tile_X0Y1_W2BEG[3]
    DIRECTION OUTPUT ;
    USE SIGNAL ;
    ANTENNADIFFAREA 0.702900 ;
    PORT
      LAYER met3 ;
        RECT 0.000 34.040 0.600 34.640 ;
    END
  END Tile_X0Y1_W2BEG[3]
  PIN Tile_X0Y1_W2BEG[4]
    DIRECTION OUTPUT ;
    USE SIGNAL ;
    ANTENNADIFFAREA 0.702900 ;
    PORT
      LAYER met3 ;
        RECT 0.000 35.400 0.600 36.000 ;
    END
  END Tile_X0Y1_W2BEG[4]
  PIN Tile_X0Y1_W2BEG[5]
    DIRECTION OUTPUT ;
    USE SIGNAL ;
    ANTENNADIFFAREA 0.702900 ;
    PORT
      LAYER met3 ;
        RECT 0.000 36.760 0.600 37.360 ;
    END
  END Tile_X0Y1_W2BEG[5]
  PIN Tile_X0Y1_W2BEG[6]
    DIRECTION OUTPUT ;
    USE SIGNAL ;
    ANTENNADIFFAREA 0.702900 ;
    PORT
      LAYER met3 ;
        RECT 0.000 38.120 0.600 38.720 ;
    END
  END Tile_X0Y1_W2BEG[6]
  PIN Tile_X0Y1_W2BEG[7]
    DIRECTION OUTPUT ;
    USE SIGNAL ;
    ANTENNADIFFAREA 0.702900 ;
    PORT
      LAYER met3 ;
        RECT 0.000 39.480 0.600 40.080 ;
    END
  END Tile_X0Y1_W2BEG[7]
  PIN Tile_X0Y1_W2BEGb[0]
    DIRECTION OUTPUT ;
    USE SIGNAL ;
    ANTENNADIFFAREA 0.702900 ;
    PORT
      LAYER met3 ;
        RECT 0.000 40.840 0.600 41.440 ;
    END
  END Tile_X0Y1_W2BEGb[0]
  PIN Tile_X0Y1_W2BEGb[1]
    DIRECTION OUTPUT ;
    USE SIGNAL ;
    ANTENNADIFFAREA 0.702900 ;
    PORT
      LAYER met3 ;
        RECT 0.000 42.200 0.600 42.800 ;
    END
  END Tile_X0Y1_W2BEGb[1]
  PIN Tile_X0Y1_W2BEGb[2]
    DIRECTION OUTPUT ;
    USE SIGNAL ;
    ANTENNADIFFAREA 0.702900 ;
    PORT
      LAYER met3 ;
        RECT 0.000 43.560 0.600 44.160 ;
    END
  END Tile_X0Y1_W2BEGb[2]
  PIN Tile_X0Y1_W2BEGb[3]
    DIRECTION OUTPUT ;
    USE SIGNAL ;
    ANTENNADIFFAREA 0.702900 ;
    PORT
      LAYER met3 ;
        RECT 0.000 44.920 0.600 45.520 ;
    END
  END Tile_X0Y1_W2BEGb[3]
  PIN Tile_X0Y1_W2BEGb[4]
    DIRECTION OUTPUT ;
    USE SIGNAL ;
    ANTENNADIFFAREA 0.702900 ;
    PORT
      LAYER met3 ;
        RECT 0.000 46.280 0.600 46.880 ;
    END
  END Tile_X0Y1_W2BEGb[4]
  PIN Tile_X0Y1_W2BEGb[5]
    DIRECTION OUTPUT ;
    USE SIGNAL ;
    ANTENNADIFFAREA 0.702900 ;
    PORT
      LAYER met3 ;
        RECT 0.000 47.640 0.600 48.240 ;
    END
  END Tile_X0Y1_W2BEGb[5]
  PIN Tile_X0Y1_W2BEGb[6]
    DIRECTION OUTPUT ;
    USE SIGNAL ;
    ANTENNADIFFAREA 0.702900 ;
    PORT
      LAYER met3 ;
        RECT 0.000 49.000 0.600 49.600 ;
    END
  END Tile_X0Y1_W2BEGb[6]
  PIN Tile_X0Y1_W2BEGb[7]
    DIRECTION OUTPUT ;
    USE SIGNAL ;
    ANTENNADIFFAREA 0.702900 ;
    PORT
      LAYER met3 ;
        RECT 0.000 50.360 0.600 50.960 ;
    END
  END Tile_X0Y1_W2BEGb[7]
  PIN Tile_X0Y1_W6BEG[0]
    DIRECTION OUTPUT ;
    USE SIGNAL ;
    ANTENNADIFFAREA 0.702900 ;
    PORT
      LAYER met3 ;
        RECT 0.000 73.480 0.600 74.080 ;
    END
  END Tile_X0Y1_W6BEG[0]
  PIN Tile_X0Y1_W6BEG[10]
    DIRECTION OUTPUT ;
    USE SIGNAL ;
    ANTENNADIFFAREA 0.702900 ;
    PORT
      LAYER met3 ;
        RECT 0.000 87.080 0.600 87.680 ;
    END
  END Tile_X0Y1_W6BEG[10]
  PIN Tile_X0Y1_W6BEG[11]
    DIRECTION OUTPUT ;
    USE SIGNAL ;
    ANTENNADIFFAREA 0.702900 ;
    PORT
      LAYER met3 ;
        RECT 0.000 88.440 0.600 89.040 ;
    END
  END Tile_X0Y1_W6BEG[11]
  PIN Tile_X0Y1_W6BEG[1]
    DIRECTION OUTPUT ;
    USE SIGNAL ;
    ANTENNADIFFAREA 0.702900 ;
    PORT
      LAYER met3 ;
        RECT 0.000 74.840 0.600 75.440 ;
    END
  END Tile_X0Y1_W6BEG[1]
  PIN Tile_X0Y1_W6BEG[2]
    DIRECTION OUTPUT ;
    USE SIGNAL ;
    ANTENNADIFFAREA 0.702900 ;
    PORT
      LAYER met3 ;
        RECT 0.000 76.200 0.600 76.800 ;
    END
  END Tile_X0Y1_W6BEG[2]
  PIN Tile_X0Y1_W6BEG[3]
    DIRECTION OUTPUT ;
    USE SIGNAL ;
    ANTENNADIFFAREA 0.702900 ;
    PORT
      LAYER met3 ;
        RECT 0.000 77.560 0.600 78.160 ;
    END
  END Tile_X0Y1_W6BEG[3]
  PIN Tile_X0Y1_W6BEG[4]
    DIRECTION OUTPUT ;
    USE SIGNAL ;
    ANTENNADIFFAREA 0.702900 ;
    PORT
      LAYER met3 ;
        RECT 0.000 78.920 0.600 79.520 ;
    END
  END Tile_X0Y1_W6BEG[4]
  PIN Tile_X0Y1_W6BEG[5]
    DIRECTION OUTPUT ;
    USE SIGNAL ;
    ANTENNADIFFAREA 0.702900 ;
    PORT
      LAYER met3 ;
        RECT 0.000 80.280 0.600 80.880 ;
    END
  END Tile_X0Y1_W6BEG[5]
  PIN Tile_X0Y1_W6BEG[6]
    DIRECTION OUTPUT ;
    USE SIGNAL ;
    ANTENNADIFFAREA 0.702900 ;
    PORT
      LAYER met3 ;
        RECT 0.000 81.640 0.600 82.240 ;
    END
  END Tile_X0Y1_W6BEG[6]
  PIN Tile_X0Y1_W6BEG[7]
    DIRECTION OUTPUT ;
    USE SIGNAL ;
    ANTENNADIFFAREA 0.702900 ;
    PORT
      LAYER met3 ;
        RECT 0.000 83.000 0.600 83.600 ;
    END
  END Tile_X0Y1_W6BEG[7]
  PIN Tile_X0Y1_W6BEG[8]
    DIRECTION OUTPUT ;
    USE SIGNAL ;
    ANTENNADIFFAREA 0.702900 ;
    PORT
      LAYER met3 ;
        RECT 0.000 84.360 0.600 84.960 ;
    END
  END Tile_X0Y1_W6BEG[8]
  PIN Tile_X0Y1_W6BEG[9]
    DIRECTION OUTPUT ;
    USE SIGNAL ;
    ANTENNADIFFAREA 0.702900 ;
    PORT
      LAYER met3 ;
        RECT 0.000 85.720 0.600 86.320 ;
    END
  END Tile_X0Y1_W6BEG[9]
  PIN Tile_X0Y1_WW4BEG[0]
    DIRECTION OUTPUT ;
    USE SIGNAL ;
    ANTENNADIFFAREA 0.702900 ;
    PORT
      LAYER met3 ;
        RECT 0.000 51.720 0.600 52.320 ;
    END
  END Tile_X0Y1_WW4BEG[0]
  PIN Tile_X0Y1_WW4BEG[10]
    DIRECTION OUTPUT ;
    USE SIGNAL ;
    ANTENNADIFFAREA 0.702900 ;
    PORT
      LAYER met3 ;
        RECT 0.000 65.320 0.600 65.920 ;
    END
  END Tile_X0Y1_WW4BEG[10]
  PIN Tile_X0Y1_WW4BEG[11]
    DIRECTION OUTPUT ;
    USE SIGNAL ;
    ANTENNADIFFAREA 0.702900 ;
    PORT
      LAYER met3 ;
        RECT 0.000 66.680 0.600 67.280 ;
    END
  END Tile_X0Y1_WW4BEG[11]
  PIN Tile_X0Y1_WW4BEG[12]
    DIRECTION OUTPUT ;
    USE SIGNAL ;
    ANTENNADIFFAREA 0.702900 ;
    PORT
      LAYER met3 ;
        RECT 0.000 68.040 0.600 68.640 ;
    END
  END Tile_X0Y1_WW4BEG[12]
  PIN Tile_X0Y1_WW4BEG[13]
    DIRECTION OUTPUT ;
    USE SIGNAL ;
    ANTENNADIFFAREA 0.702900 ;
    PORT
      LAYER met3 ;
        RECT 0.000 69.400 0.600 70.000 ;
    END
  END Tile_X0Y1_WW4BEG[13]
  PIN Tile_X0Y1_WW4BEG[14]
    DIRECTION OUTPUT ;
    USE SIGNAL ;
    ANTENNADIFFAREA 0.702900 ;
    PORT
      LAYER met3 ;
        RECT 0.000 70.760 0.600 71.360 ;
    END
  END Tile_X0Y1_WW4BEG[14]
  PIN Tile_X0Y1_WW4BEG[15]
    DIRECTION OUTPUT ;
    USE SIGNAL ;
    ANTENNADIFFAREA 0.702900 ;
    PORT
      LAYER met3 ;
        RECT 0.000 72.120 0.600 72.720 ;
    END
  END Tile_X0Y1_WW4BEG[15]
  PIN Tile_X0Y1_WW4BEG[1]
    DIRECTION OUTPUT ;
    USE SIGNAL ;
    ANTENNADIFFAREA 0.702900 ;
    PORT
      LAYER met3 ;
        RECT 0.000 53.080 0.600 53.680 ;
    END
  END Tile_X0Y1_WW4BEG[1]
  PIN Tile_X0Y1_WW4BEG[2]
    DIRECTION OUTPUT ;
    USE SIGNAL ;
    ANTENNADIFFAREA 0.702900 ;
    PORT
      LAYER met3 ;
        RECT 0.000 54.440 0.600 55.040 ;
    END
  END Tile_X0Y1_WW4BEG[2]
  PIN Tile_X0Y1_WW4BEG[3]
    DIRECTION OUTPUT ;
    USE SIGNAL ;
    ANTENNADIFFAREA 0.702900 ;
    PORT
      LAYER met3 ;
        RECT 0.000 55.800 0.600 56.400 ;
    END
  END Tile_X0Y1_WW4BEG[3]
  PIN Tile_X0Y1_WW4BEG[4]
    DIRECTION OUTPUT ;
    USE SIGNAL ;
    ANTENNADIFFAREA 0.702900 ;
    PORT
      LAYER met3 ;
        RECT 0.000 57.160 0.600 57.760 ;
    END
  END Tile_X0Y1_WW4BEG[4]
  PIN Tile_X0Y1_WW4BEG[5]
    DIRECTION OUTPUT ;
    USE SIGNAL ;
    ANTENNADIFFAREA 0.702900 ;
    PORT
      LAYER met3 ;
        RECT 0.000 58.520 0.600 59.120 ;
    END
  END Tile_X0Y1_WW4BEG[5]
  PIN Tile_X0Y1_WW4BEG[6]
    DIRECTION OUTPUT ;
    USE SIGNAL ;
    ANTENNADIFFAREA 0.702900 ;
    PORT
      LAYER met3 ;
        RECT 0.000 59.880 0.600 60.480 ;
    END
  END Tile_X0Y1_WW4BEG[6]
  PIN Tile_X0Y1_WW4BEG[7]
    DIRECTION OUTPUT ;
    USE SIGNAL ;
    ANTENNADIFFAREA 0.702900 ;
    PORT
      LAYER met3 ;
        RECT 0.000 61.240 0.600 61.840 ;
    END
  END Tile_X0Y1_WW4BEG[7]
  PIN Tile_X0Y1_WW4BEG[8]
    DIRECTION OUTPUT ;
    USE SIGNAL ;
    ANTENNADIFFAREA 0.702900 ;
    PORT
      LAYER met3 ;
        RECT 0.000 62.600 0.600 63.200 ;
    END
  END Tile_X0Y1_WW4BEG[8]
  PIN Tile_X0Y1_WW4BEG[9]
    DIRECTION OUTPUT ;
    USE SIGNAL ;
    ANTENNADIFFAREA 0.702900 ;
    PORT
      LAYER met3 ;
        RECT 0.000 63.960 0.600 64.560 ;
    END
  END Tile_X0Y1_WW4BEG[9]
  PIN UIO_IN_TT_PROJECT0
    DIRECTION OUTPUT ;
    USE SIGNAL ;
    ANTENNADIFFAREA 0.702900 ;
    PORT
      LAYER met3 ;
        RECT 64.720 103.400 65.320 104.000 ;
    END
  END UIO_IN_TT_PROJECT0
  PIN UIO_IN_TT_PROJECT1
    DIRECTION OUTPUT ;
    USE SIGNAL ;
    ANTENNADIFFAREA 0.702900 ;
    PORT
      LAYER met3 ;
        RECT 64.720 106.120 65.320 106.720 ;
    END
  END UIO_IN_TT_PROJECT1
  PIN UIO_IN_TT_PROJECT2
    DIRECTION OUTPUT ;
    USE SIGNAL ;
    ANTENNADIFFAREA 0.702900 ;
    PORT
      LAYER met3 ;
        RECT 64.720 108.840 65.320 109.440 ;
    END
  END UIO_IN_TT_PROJECT2
  PIN UIO_IN_TT_PROJECT3
    DIRECTION OUTPUT ;
    USE SIGNAL ;
    ANTENNADIFFAREA 0.702900 ;
    PORT
      LAYER met3 ;
        RECT 64.720 111.560 65.320 112.160 ;
    END
  END UIO_IN_TT_PROJECT3
  PIN UIO_IN_TT_PROJECT4
    DIRECTION OUTPUT ;
    USE SIGNAL ;
    ANTENNADIFFAREA 0.702900 ;
    PORT
      LAYER met3 ;
        RECT 64.720 114.280 65.320 114.880 ;
    END
  END UIO_IN_TT_PROJECT4
  PIN UIO_IN_TT_PROJECT5
    DIRECTION OUTPUT ;
    USE SIGNAL ;
    ANTENNADIFFAREA 0.702900 ;
    PORT
      LAYER met3 ;
        RECT 64.720 117.000 65.320 117.600 ;
    END
  END UIO_IN_TT_PROJECT5
  PIN UIO_IN_TT_PROJECT6
    DIRECTION OUTPUT ;
    USE SIGNAL ;
    ANTENNADIFFAREA 0.702900 ;
    PORT
      LAYER met3 ;
        RECT 64.720 119.720 65.320 120.320 ;
    END
  END UIO_IN_TT_PROJECT6
  PIN UIO_IN_TT_PROJECT7
    DIRECTION OUTPUT ;
    USE SIGNAL ;
    ANTENNADIFFAREA 0.702900 ;
    PORT
      LAYER met3 ;
        RECT 64.720 122.440 65.320 123.040 ;
    END
  END UIO_IN_TT_PROJECT7
  PIN UIO_OE_TT_PROJECT0
    DIRECTION INPUT ;
    USE SIGNAL ;
    ANTENNAGATEAREA 1.557000 ;
    PORT
      LAYER met3 ;
        RECT 64.720 59.880 65.320 60.480 ;
    END
  END UIO_OE_TT_PROJECT0
  PIN UIO_OE_TT_PROJECT1
    DIRECTION INPUT ;
    USE SIGNAL ;
    ANTENNAGATEAREA 1.557000 ;
    PORT
      LAYER met3 ;
        RECT 64.720 62.600 65.320 63.200 ;
    END
  END UIO_OE_TT_PROJECT1
  PIN UIO_OE_TT_PROJECT2
    DIRECTION INPUT ;
    USE SIGNAL ;
    ANTENNAGATEAREA 1.557000 ;
    PORT
      LAYER met3 ;
        RECT 64.720 65.320 65.320 65.920 ;
    END
  END UIO_OE_TT_PROJECT2
  PIN UIO_OE_TT_PROJECT3
    DIRECTION INPUT ;
    USE SIGNAL ;
    ANTENNAGATEAREA 2.426400 ;
    ANTENNADIFFAREA 0.869400 ;
    PORT
      LAYER met3 ;
        RECT 64.720 68.040 65.320 68.640 ;
    END
  END UIO_OE_TT_PROJECT3
  PIN UIO_OE_TT_PROJECT4
    DIRECTION INPUT ;
    USE SIGNAL ;
    ANTENNAGATEAREA 1.991700 ;
    ANTENNADIFFAREA 0.434700 ;
    PORT
      LAYER met3 ;
        RECT 64.720 70.760 65.320 71.360 ;
    END
  END UIO_OE_TT_PROJECT4
  PIN UIO_OE_TT_PROJECT5
    DIRECTION INPUT ;
    USE SIGNAL ;
    ANTENNAGATEAREA 2.861100 ;
    ANTENNADIFFAREA 1.304100 ;
    PORT
      LAYER met3 ;
        RECT 64.720 73.480 65.320 74.080 ;
    END
  END UIO_OE_TT_PROJECT5
  PIN UIO_OE_TT_PROJECT6
    DIRECTION INPUT ;
    USE SIGNAL ;
    ANTENNAGATEAREA 1.557000 ;
    PORT
      LAYER met3 ;
        RECT 64.720 76.200 65.320 76.800 ;
    END
  END UIO_OE_TT_PROJECT6
  PIN UIO_OE_TT_PROJECT7
    DIRECTION INPUT ;
    USE SIGNAL ;
    ANTENNAGATEAREA 1.557000 ;
    PORT
      LAYER met3 ;
        RECT 64.720 78.920 65.320 79.520 ;
    END
  END UIO_OE_TT_PROJECT7
  PIN UIO_OUT_TT_PROJECT0
    DIRECTION INPUT ;
    USE SIGNAL ;
    ANTENNAGATEAREA 2.160000 ;
    PORT
      LAYER met3 ;
        RECT 64.720 38.120 65.320 38.720 ;
    END
  END UIO_OUT_TT_PROJECT0
  PIN UIO_OUT_TT_PROJECT1
    DIRECTION INPUT ;
    USE SIGNAL ;
    ANTENNAGATEAREA 2.160000 ;
    PORT
      LAYER met3 ;
        RECT 64.720 40.840 65.320 41.440 ;
    END
  END UIO_OUT_TT_PROJECT1
  PIN UIO_OUT_TT_PROJECT2
    DIRECTION INPUT ;
    USE SIGNAL ;
    ANTENNAGATEAREA 2.160000 ;
    PORT
      LAYER met3 ;
        RECT 64.720 43.560 65.320 44.160 ;
    END
  END UIO_OUT_TT_PROJECT2
  PIN UIO_OUT_TT_PROJECT3
    DIRECTION INPUT ;
    USE SIGNAL ;
    ANTENNAGATEAREA 3.029400 ;
    ANTENNADIFFAREA 0.869400 ;
    PORT
      LAYER met3 ;
        RECT 64.720 46.280 65.320 46.880 ;
    END
  END UIO_OUT_TT_PROJECT3
  PIN UIO_OUT_TT_PROJECT4
    DIRECTION INPUT ;
    USE SIGNAL ;
    ANTENNAGATEAREA 2.160000 ;
    PORT
      LAYER met3 ;
        RECT 64.720 49.000 65.320 49.600 ;
    END
  END UIO_OUT_TT_PROJECT4
  PIN UIO_OUT_TT_PROJECT5
    DIRECTION INPUT ;
    USE SIGNAL ;
    ANTENNAGATEAREA 2.160000 ;
    PORT
      LAYER met3 ;
        RECT 64.720 51.720 65.320 52.320 ;
    END
  END UIO_OUT_TT_PROJECT5
  PIN UIO_OUT_TT_PROJECT6
    DIRECTION INPUT ;
    USE SIGNAL ;
    ANTENNAGATEAREA 2.160000 ;
    PORT
      LAYER met3 ;
        RECT 64.720 54.440 65.320 55.040 ;
    END
  END UIO_OUT_TT_PROJECT6
  PIN UIO_OUT_TT_PROJECT7
    DIRECTION INPUT ;
    USE SIGNAL ;
    ANTENNAGATEAREA 2.160000 ;
    PORT
      LAYER met3 ;
        RECT 64.720 57.160 65.320 57.760 ;
    END
  END UIO_OUT_TT_PROJECT7
  PIN UI_IN_TT_PROJECT0
    DIRECTION OUTPUT ;
    USE SIGNAL ;
    ANTENNADIFFAREA 0.702900 ;
    PORT
      LAYER met3 ;
        RECT 64.720 81.640 65.320 82.240 ;
    END
  END UI_IN_TT_PROJECT0
  PIN UI_IN_TT_PROJECT1
    DIRECTION OUTPUT ;
    USE SIGNAL ;
    ANTENNADIFFAREA 0.702900 ;
    PORT
      LAYER met3 ;
        RECT 64.720 84.360 65.320 84.960 ;
    END
  END UI_IN_TT_PROJECT1
  PIN UI_IN_TT_PROJECT2
    DIRECTION OUTPUT ;
    USE SIGNAL ;
    ANTENNADIFFAREA 0.702900 ;
    PORT
      LAYER met3 ;
        RECT 64.720 87.080 65.320 87.680 ;
    END
  END UI_IN_TT_PROJECT2
  PIN UI_IN_TT_PROJECT3
    DIRECTION OUTPUT ;
    USE SIGNAL ;
    ANTENNADIFFAREA 0.702900 ;
    PORT
      LAYER met3 ;
        RECT 64.720 89.800 65.320 90.400 ;
    END
  END UI_IN_TT_PROJECT3
  PIN UI_IN_TT_PROJECT4
    DIRECTION OUTPUT ;
    USE SIGNAL ;
    ANTENNADIFFAREA 0.702900 ;
    PORT
      LAYER met3 ;
        RECT 64.720 92.520 65.320 93.120 ;
    END
  END UI_IN_TT_PROJECT4
  PIN UI_IN_TT_PROJECT5
    DIRECTION OUTPUT ;
    USE SIGNAL ;
    ANTENNADIFFAREA 0.702900 ;
    PORT
      LAYER met3 ;
        RECT 64.720 95.240 65.320 95.840 ;
    END
  END UI_IN_TT_PROJECT5
  PIN UI_IN_TT_PROJECT6
    DIRECTION OUTPUT ;
    USE SIGNAL ;
    ANTENNADIFFAREA 0.702900 ;
    PORT
      LAYER met3 ;
        RECT 64.720 97.960 65.320 98.560 ;
    END
  END UI_IN_TT_PROJECT6
  PIN UI_IN_TT_PROJECT7
    DIRECTION OUTPUT ;
    USE SIGNAL ;
    ANTENNADIFFAREA 0.702900 ;
    PORT
      LAYER met3 ;
        RECT 64.720 100.680 65.320 101.280 ;
    END
  END UI_IN_TT_PROJECT7
  PIN UO_OUT_TT_PROJECT0
    DIRECTION INPUT ;
    USE SIGNAL ;
    ANTENNAGATEAREA 1.355700 ;
    ANTENNADIFFAREA 0.434700 ;
    PORT
      LAYER met3 ;
        RECT 64.720 16.360 65.320 16.960 ;
    END
  END UO_OUT_TT_PROJECT0
  PIN UO_OUT_TT_PROJECT1
    DIRECTION INPUT ;
    USE SIGNAL ;
    ANTENNAGATEAREA 1.355700 ;
    ANTENNADIFFAREA 0.434700 ;
    PORT
      LAYER met3 ;
        RECT 64.720 19.080 65.320 19.680 ;
    END
  END UO_OUT_TT_PROJECT1
  PIN UO_OUT_TT_PROJECT2
    DIRECTION INPUT ;
    USE SIGNAL ;
    ANTENNAGATEAREA 0.921000 ;
    PORT
      LAYER met3 ;
        RECT 64.720 21.800 65.320 22.400 ;
    END
  END UO_OUT_TT_PROJECT2
  PIN UO_OUT_TT_PROJECT3
    DIRECTION INPUT ;
    USE SIGNAL ;
    ANTENNAGATEAREA 0.921000 ;
    PORT
      LAYER met3 ;
        RECT 64.720 24.520 65.320 25.120 ;
    END
  END UO_OUT_TT_PROJECT3
  PIN UO_OUT_TT_PROJECT4
    DIRECTION INPUT ;
    USE SIGNAL ;
    ANTENNAGATEAREA 0.921000 ;
    PORT
      LAYER met3 ;
        RECT 64.720 27.240 65.320 27.840 ;
    END
  END UO_OUT_TT_PROJECT4
  PIN UO_OUT_TT_PROJECT5
    DIRECTION INPUT ;
    USE SIGNAL ;
    ANTENNAGATEAREA 0.921000 ;
    PORT
      LAYER met3 ;
        RECT 64.720 29.960 65.320 30.560 ;
    END
  END UO_OUT_TT_PROJECT5
  PIN UO_OUT_TT_PROJECT6
    DIRECTION INPUT ;
    USE SIGNAL ;
    ANTENNAGATEAREA 0.921000 ;
    PORT
      LAYER met3 ;
        RECT 64.720 32.680 65.320 33.280 ;
    END
  END UO_OUT_TT_PROJECT6
  PIN UO_OUT_TT_PROJECT7
    DIRECTION INPUT ;
    USE SIGNAL ;
    ANTENNAGATEAREA 0.921000 ;
    PORT
      LAYER met3 ;
        RECT 64.720 35.400 65.320 36.000 ;
    END
  END UO_OUT_TT_PROJECT7
  PIN VGND
    DIRECTION INOUT ;
    USE GROUND ;
    PORT
      LAYER met4 ;
        RECT 12.260 0.000 13.860 446.080 ;
    END
    PORT
      LAYER met4 ;
        RECT 42.260 0.000 43.860 446.080 ;
    END
  END VGND
  PIN VPWR
    DIRECTION INOUT ;
    USE POWER ;
    PORT
      LAYER met4 ;
        RECT 6.960 0.000 8.560 446.080 ;
    END
    PORT
      LAYER met4 ;
        RECT 36.960 0.000 38.560 446.080 ;
    END
  END VPWR
  OBS
      LAYER nwell ;
        RECT 2.570 2.635 62.750 443.445 ;
      LAYER li1 ;
        RECT 2.760 2.635 62.560 443.445 ;
      LAYER met1 ;
        RECT 0.530 2.080 63.870 443.600 ;
      LAYER met2 ;
        RECT 0.160 445.520 5.790 445.810 ;
        RECT 6.630 445.520 8.090 445.810 ;
        RECT 8.930 445.520 10.390 445.810 ;
        RECT 11.230 445.520 12.690 445.810 ;
        RECT 13.530 445.520 14.990 445.810 ;
        RECT 15.830 445.520 17.290 445.810 ;
        RECT 18.130 445.520 19.590 445.810 ;
        RECT 20.430 445.520 21.890 445.810 ;
        RECT 22.730 445.520 24.190 445.810 ;
        RECT 25.030 445.520 26.490 445.810 ;
        RECT 27.330 445.520 28.790 445.810 ;
        RECT 29.630 445.520 31.090 445.810 ;
        RECT 31.930 445.520 33.390 445.810 ;
        RECT 34.230 445.520 35.690 445.810 ;
        RECT 36.530 445.520 37.990 445.810 ;
        RECT 38.830 445.520 40.290 445.810 ;
        RECT 41.130 445.520 42.590 445.810 ;
        RECT 43.430 445.520 44.890 445.810 ;
        RECT 45.730 445.520 47.190 445.810 ;
        RECT 48.030 445.520 49.490 445.810 ;
        RECT 50.330 445.520 51.790 445.810 ;
        RECT 52.630 445.520 54.090 445.810 ;
        RECT 54.930 445.520 56.390 445.810 ;
        RECT 57.230 445.520 58.690 445.810 ;
        RECT 59.530 445.520 64.770 445.810 ;
        RECT 0.160 0.560 64.770 445.520 ;
        RECT 0.160 0.270 5.790 0.560 ;
        RECT 6.630 0.270 8.090 0.560 ;
        RECT 8.930 0.270 10.390 0.560 ;
        RECT 11.230 0.270 12.690 0.560 ;
        RECT 13.530 0.270 14.990 0.560 ;
        RECT 15.830 0.270 17.290 0.560 ;
        RECT 18.130 0.270 19.590 0.560 ;
        RECT 20.430 0.270 21.890 0.560 ;
        RECT 22.730 0.270 24.190 0.560 ;
        RECT 25.030 0.270 26.490 0.560 ;
        RECT 27.330 0.270 28.790 0.560 ;
        RECT 29.630 0.270 31.090 0.560 ;
        RECT 31.930 0.270 33.390 0.560 ;
        RECT 34.230 0.270 35.690 0.560 ;
        RECT 36.530 0.270 37.990 0.560 ;
        RECT 38.830 0.270 40.290 0.560 ;
        RECT 41.130 0.270 42.590 0.560 ;
        RECT 43.430 0.270 44.890 0.560 ;
        RECT 45.730 0.270 47.190 0.560 ;
        RECT 48.030 0.270 49.490 0.560 ;
        RECT 50.330 0.270 51.790 0.560 ;
        RECT 52.630 0.270 54.090 0.560 ;
        RECT 54.930 0.270 56.390 0.560 ;
        RECT 57.230 0.270 58.690 0.560 ;
        RECT 59.530 0.270 64.770 0.560 ;
      LAYER met3 ;
        RECT 0.600 434.200 64.795 443.525 ;
        RECT 0.600 432.800 64.320 434.200 ;
        RECT 0.600 430.120 64.795 432.800 ;
        RECT 0.600 428.720 64.320 430.120 ;
        RECT 0.600 426.040 64.795 428.720 ;
        RECT 0.600 424.640 64.320 426.040 ;
        RECT 0.600 421.960 64.795 424.640 ;
        RECT 0.600 421.280 64.320 421.960 ;
        RECT 1.000 420.560 64.320 421.280 ;
        RECT 1.000 417.880 64.795 420.560 ;
        RECT 1.000 416.480 64.320 417.880 ;
        RECT 1.000 413.800 64.795 416.480 ;
        RECT 1.000 412.400 64.320 413.800 ;
        RECT 1.000 409.720 64.795 412.400 ;
        RECT 1.000 408.320 64.320 409.720 ;
        RECT 1.000 405.640 64.795 408.320 ;
        RECT 1.000 404.240 64.320 405.640 ;
        RECT 1.000 401.560 64.795 404.240 ;
        RECT 1.000 400.160 64.320 401.560 ;
        RECT 1.000 397.480 64.795 400.160 ;
        RECT 1.000 396.080 64.320 397.480 ;
        RECT 1.000 393.400 64.795 396.080 ;
        RECT 1.000 392.000 64.320 393.400 ;
        RECT 1.000 389.320 64.795 392.000 ;
        RECT 1.000 387.920 64.320 389.320 ;
        RECT 1.000 385.240 64.795 387.920 ;
        RECT 1.000 383.840 64.320 385.240 ;
        RECT 1.000 381.160 64.795 383.840 ;
        RECT 1.000 379.760 64.320 381.160 ;
        RECT 1.000 377.080 64.795 379.760 ;
        RECT 1.000 375.680 64.320 377.080 ;
        RECT 1.000 373.000 64.795 375.680 ;
        RECT 1.000 371.600 64.320 373.000 ;
        RECT 1.000 368.920 64.795 371.600 ;
        RECT 1.000 367.520 64.320 368.920 ;
        RECT 1.000 364.840 64.795 367.520 ;
        RECT 1.000 363.440 64.320 364.840 ;
        RECT 1.000 360.760 64.795 363.440 ;
        RECT 1.000 359.360 64.320 360.760 ;
        RECT 1.000 356.680 64.795 359.360 ;
        RECT 1.000 355.280 64.320 356.680 ;
        RECT 1.000 352.600 64.795 355.280 ;
        RECT 1.000 351.200 64.320 352.600 ;
        RECT 1.000 348.520 64.795 351.200 ;
        RECT 1.000 347.120 64.320 348.520 ;
        RECT 1.000 344.440 64.795 347.120 ;
        RECT 1.000 343.040 64.320 344.440 ;
        RECT 1.000 340.360 64.795 343.040 ;
        RECT 1.000 338.960 64.320 340.360 ;
        RECT 1.000 336.280 64.795 338.960 ;
        RECT 1.000 334.880 64.320 336.280 ;
        RECT 1.000 332.200 64.795 334.880 ;
        RECT 1.000 330.800 64.320 332.200 ;
        RECT 1.000 328.120 64.795 330.800 ;
        RECT 1.000 326.720 64.320 328.120 ;
        RECT 1.000 324.040 64.795 326.720 ;
        RECT 1.000 322.640 64.320 324.040 ;
        RECT 1.000 319.960 64.795 322.640 ;
        RECT 1.000 318.560 64.320 319.960 ;
        RECT 1.000 315.880 64.795 318.560 ;
        RECT 1.000 314.480 64.320 315.880 ;
        RECT 1.000 311.800 64.795 314.480 ;
        RECT 1.000 310.400 64.320 311.800 ;
        RECT 1.000 307.720 64.795 310.400 ;
        RECT 1.000 306.320 64.320 307.720 ;
        RECT 1.000 285.280 64.795 306.320 ;
        RECT 1.000 283.880 64.320 285.280 ;
        RECT 1.000 281.200 64.795 283.880 ;
        RECT 1.000 279.800 64.320 281.200 ;
        RECT 1.000 277.120 64.795 279.800 ;
        RECT 1.000 275.720 64.320 277.120 ;
        RECT 1.000 273.040 64.795 275.720 ;
        RECT 1.000 271.640 64.320 273.040 ;
        RECT 1.000 268.960 64.795 271.640 ;
        RECT 1.000 267.560 64.320 268.960 ;
        RECT 1.000 264.880 64.795 267.560 ;
        RECT 1.000 263.480 64.320 264.880 ;
        RECT 1.000 260.800 64.795 263.480 ;
        RECT 1.000 259.400 64.320 260.800 ;
        RECT 1.000 256.720 64.795 259.400 ;
        RECT 1.000 255.320 64.320 256.720 ;
        RECT 1.000 252.640 64.795 255.320 ;
        RECT 1.000 251.240 64.320 252.640 ;
        RECT 1.000 248.560 64.795 251.240 ;
        RECT 1.000 247.160 64.320 248.560 ;
        RECT 0.600 244.480 64.795 247.160 ;
        RECT 0.600 243.080 64.320 244.480 ;
        RECT 0.600 240.400 64.795 243.080 ;
        RECT 0.600 239.000 64.320 240.400 ;
        RECT 0.600 236.320 64.795 239.000 ;
        RECT 0.600 234.920 64.320 236.320 ;
        RECT 0.600 232.240 64.795 234.920 ;
        RECT 0.600 230.840 64.320 232.240 ;
        RECT 0.600 228.160 64.795 230.840 ;
        RECT 0.600 226.760 64.320 228.160 ;
        RECT 0.600 224.080 64.795 226.760 ;
        RECT 0.600 222.680 64.320 224.080 ;
        RECT 0.600 220.000 64.795 222.680 ;
        RECT 0.600 218.600 64.320 220.000 ;
        RECT 0.600 215.920 64.795 218.600 ;
        RECT 0.600 214.520 64.320 215.920 ;
        RECT 0.600 211.840 64.795 214.520 ;
        RECT 0.600 210.440 64.320 211.840 ;
        RECT 0.600 207.760 64.795 210.440 ;
        RECT 0.600 206.360 64.320 207.760 ;
        RECT 0.600 203.680 64.795 206.360 ;
        RECT 0.600 202.280 64.320 203.680 ;
        RECT 0.600 199.600 64.795 202.280 ;
        RECT 0.600 198.240 64.320 199.600 ;
        RECT 1.000 198.200 64.320 198.240 ;
        RECT 1.000 195.520 64.795 198.200 ;
        RECT 1.000 194.120 64.320 195.520 ;
        RECT 1.000 191.440 64.795 194.120 ;
        RECT 1.000 190.040 64.320 191.440 ;
        RECT 1.000 187.360 64.795 190.040 ;
        RECT 1.000 185.960 64.320 187.360 ;
        RECT 1.000 183.280 64.795 185.960 ;
        RECT 1.000 181.880 64.320 183.280 ;
        RECT 1.000 179.200 64.795 181.880 ;
        RECT 1.000 177.800 64.320 179.200 ;
        RECT 1.000 175.120 64.795 177.800 ;
        RECT 1.000 173.720 64.320 175.120 ;
        RECT 1.000 171.040 64.795 173.720 ;
        RECT 1.000 169.640 64.320 171.040 ;
        RECT 1.000 166.960 64.795 169.640 ;
        RECT 1.000 165.560 64.320 166.960 ;
        RECT 1.000 162.880 64.795 165.560 ;
        RECT 1.000 161.480 64.320 162.880 ;
        RECT 1.000 158.800 64.795 161.480 ;
        RECT 1.000 157.400 64.320 158.800 ;
        RECT 1.000 131.600 64.795 157.400 ;
        RECT 1.000 130.200 64.320 131.600 ;
        RECT 1.000 128.880 64.795 130.200 ;
        RECT 1.000 127.480 64.320 128.880 ;
        RECT 1.000 126.160 64.795 127.480 ;
        RECT 1.000 124.760 64.320 126.160 ;
        RECT 1.000 123.440 64.795 124.760 ;
        RECT 1.000 122.040 64.320 123.440 ;
        RECT 1.000 120.720 64.795 122.040 ;
        RECT 1.000 119.320 64.320 120.720 ;
        RECT 1.000 118.000 64.795 119.320 ;
        RECT 1.000 116.600 64.320 118.000 ;
        RECT 1.000 115.280 64.795 116.600 ;
        RECT 1.000 113.880 64.320 115.280 ;
        RECT 1.000 112.560 64.795 113.880 ;
        RECT 1.000 111.160 64.320 112.560 ;
        RECT 1.000 109.840 64.795 111.160 ;
        RECT 1.000 108.440 64.320 109.840 ;
        RECT 1.000 107.120 64.795 108.440 ;
        RECT 1.000 105.720 64.320 107.120 ;
        RECT 1.000 104.400 64.795 105.720 ;
        RECT 1.000 103.000 64.320 104.400 ;
        RECT 1.000 101.680 64.795 103.000 ;
        RECT 1.000 100.280 64.320 101.680 ;
        RECT 1.000 98.960 64.795 100.280 ;
        RECT 1.000 97.560 64.320 98.960 ;
        RECT 1.000 96.240 64.795 97.560 ;
        RECT 1.000 94.840 64.320 96.240 ;
        RECT 1.000 93.520 64.795 94.840 ;
        RECT 1.000 92.120 64.320 93.520 ;
        RECT 1.000 90.800 64.795 92.120 ;
        RECT 1.000 89.400 64.320 90.800 ;
        RECT 1.000 88.080 64.795 89.400 ;
        RECT 1.000 86.680 64.320 88.080 ;
        RECT 1.000 85.360 64.795 86.680 ;
        RECT 1.000 83.960 64.320 85.360 ;
        RECT 1.000 82.640 64.795 83.960 ;
        RECT 1.000 81.240 64.320 82.640 ;
        RECT 1.000 79.920 64.795 81.240 ;
        RECT 1.000 78.520 64.320 79.920 ;
        RECT 1.000 77.200 64.795 78.520 ;
        RECT 1.000 75.800 64.320 77.200 ;
        RECT 1.000 74.480 64.795 75.800 ;
        RECT 1.000 73.080 64.320 74.480 ;
        RECT 1.000 71.760 64.795 73.080 ;
        RECT 1.000 70.360 64.320 71.760 ;
        RECT 1.000 69.040 64.795 70.360 ;
        RECT 1.000 67.640 64.320 69.040 ;
        RECT 1.000 66.320 64.795 67.640 ;
        RECT 1.000 64.920 64.320 66.320 ;
        RECT 1.000 63.600 64.795 64.920 ;
        RECT 1.000 62.200 64.320 63.600 ;
        RECT 1.000 60.880 64.795 62.200 ;
        RECT 1.000 59.480 64.320 60.880 ;
        RECT 1.000 58.160 64.795 59.480 ;
        RECT 1.000 56.760 64.320 58.160 ;
        RECT 1.000 55.440 64.795 56.760 ;
        RECT 1.000 54.040 64.320 55.440 ;
        RECT 1.000 52.720 64.795 54.040 ;
        RECT 1.000 51.320 64.320 52.720 ;
        RECT 1.000 50.000 64.795 51.320 ;
        RECT 1.000 48.600 64.320 50.000 ;
        RECT 1.000 47.280 64.795 48.600 ;
        RECT 1.000 45.880 64.320 47.280 ;
        RECT 1.000 44.560 64.795 45.880 ;
        RECT 1.000 43.160 64.320 44.560 ;
        RECT 1.000 41.840 64.795 43.160 ;
        RECT 1.000 40.440 64.320 41.840 ;
        RECT 1.000 39.120 64.795 40.440 ;
        RECT 1.000 37.720 64.320 39.120 ;
        RECT 1.000 36.400 64.795 37.720 ;
        RECT 1.000 35.000 64.320 36.400 ;
        RECT 1.000 33.680 64.795 35.000 ;
        RECT 1.000 32.280 64.320 33.680 ;
        RECT 1.000 30.960 64.795 32.280 ;
        RECT 1.000 29.560 64.320 30.960 ;
        RECT 1.000 28.240 64.795 29.560 ;
        RECT 1.000 26.840 64.320 28.240 ;
        RECT 1.000 25.520 64.795 26.840 ;
        RECT 1.000 24.120 64.320 25.520 ;
        RECT 0.600 22.800 64.795 24.120 ;
        RECT 0.600 21.400 64.320 22.800 ;
        RECT 0.600 20.080 64.795 21.400 ;
        RECT 0.600 18.680 64.320 20.080 ;
        RECT 0.600 17.360 64.795 18.680 ;
        RECT 0.600 15.960 64.320 17.360 ;
        RECT 0.600 2.555 64.795 15.960 ;
      LAYER met4 ;
        RECT 0.310 6.295 6.560 439.105 ;
        RECT 8.960 6.295 11.860 439.105 ;
        RECT 14.260 6.295 36.560 439.105 ;
        RECT 38.960 6.295 41.860 439.105 ;
        RECT 44.260 6.295 65.010 439.105 ;
  END
END E_TT_IF2
END LIBRARY

